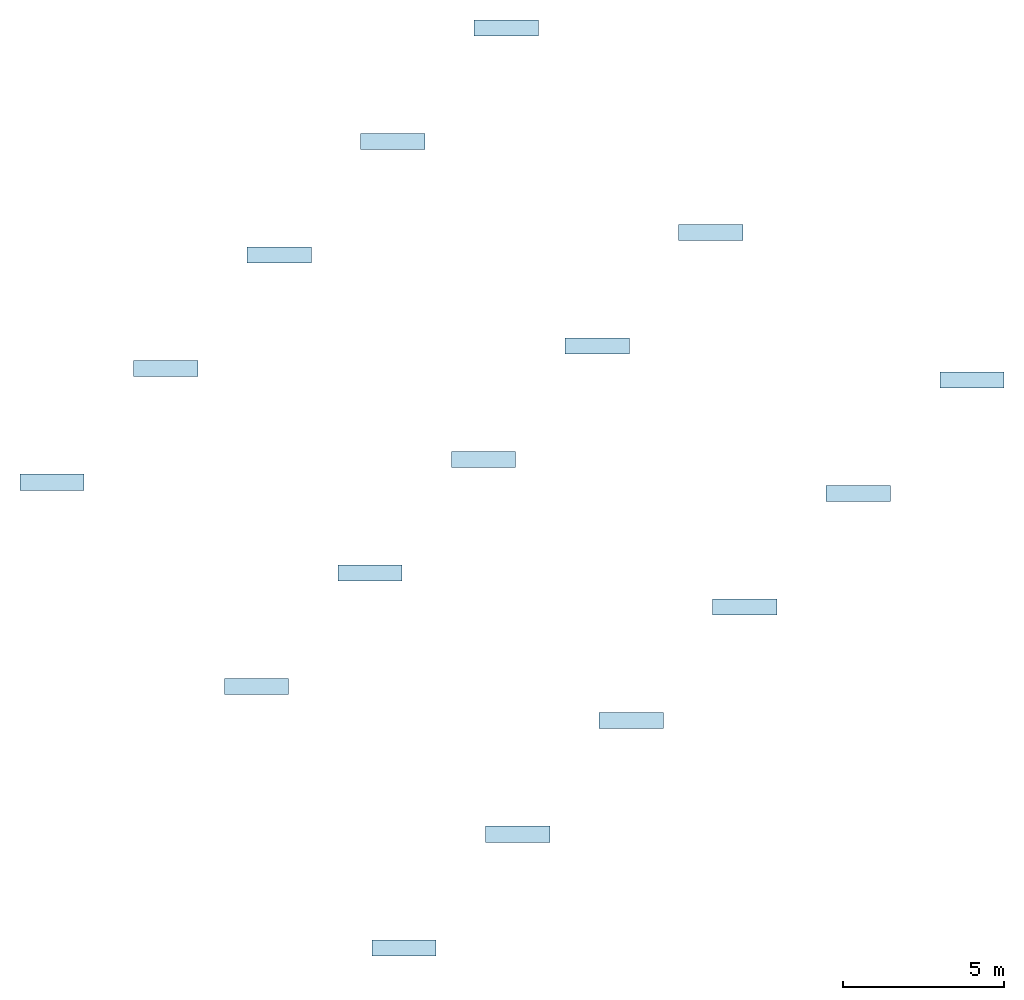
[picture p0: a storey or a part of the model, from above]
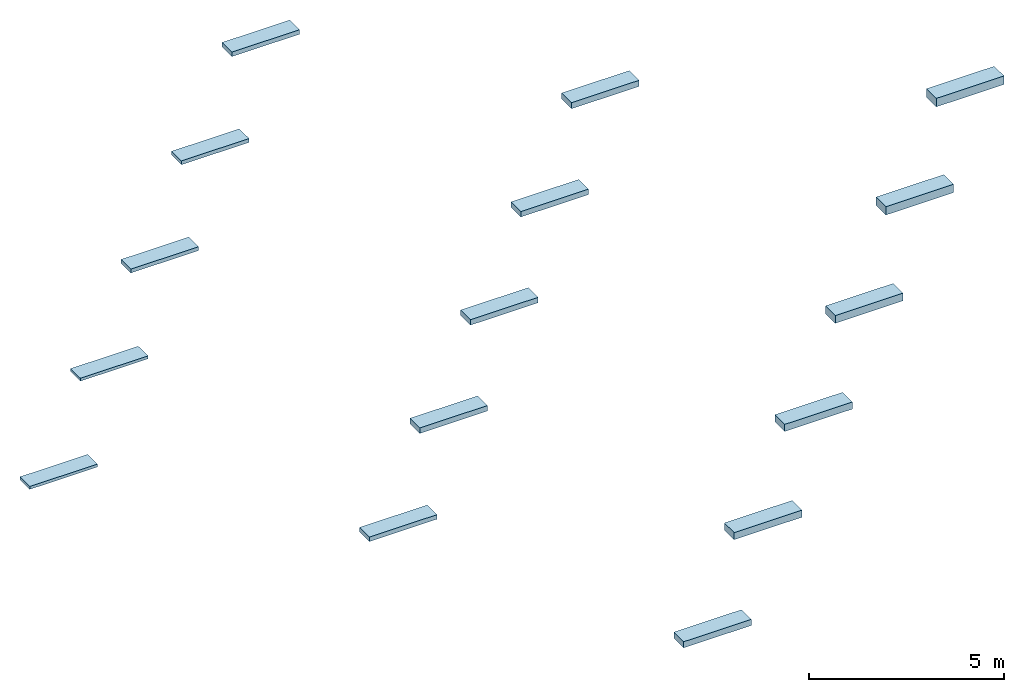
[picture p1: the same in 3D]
Properties of the parts of a building model (IFC2X3), part 2 of 3

# IfcSlab: Floor:NLRS_23_FL_Naturoll 037_120x580x6500mm, Floor:NLRS_23_FL_Naturoll 037_120x580x6500mm:13054
Type - Pset_ReinforcementBarPitchOfSlab - Description: Naturoll 037 - 120mm; Reference: NLRS_23_FL_Naturoll 037_120x580x6500mm
Type - Pset_SlabCommon - IsExternal: no; Reference: NLRS_23_FL_Naturoll 037_120x580x6500mm; ThermalTransmittance: 0.291667 kg/K/s3
Classification: 23 Vloeren (Uniformat)
Pset_SlabCommon - LoadBearing: no; PitchAngle: 0 deg
BaseQuantities - GrossArea: 1 m2; NetArea: 2.6 m2; GrossVolume: 120 m3; NetVolume: 0.12 m3; Perimeter: 5000 mm; Width: 120 mm
Constraints - Height Offset From Level: 0 mm; Level: Level: Begane grond; Related to Mass: no; Room Bounding: yes
Dimensions - Elevation at Top: 0 mm; Area: 1 m2; Elevation at Bottom: -120 mm; Perimeter: 5000 mm; Thickness: 120 mm; Volume: 0.12 m3
Other - Family: Floor: NLRS_23_FL_Naturoll 037_120x580x6500mm; Family and Type: Floor: NLRS_23_FL_Naturoll 037_120x580x6500mm; Type: Floor: NLRS_23_FL_Naturoll 037_120x580x6500mm; Type Id: Floor: NLRS_23_FL_Naturoll 037_120x580x6500mm
Phasing - Phase Created: New Construction
Structural - Enable Analytical Model: no; Structural: no

# IfcSlab: Floor:NLRS_23_FL_Naturoll 037_140x380x5600mm, Floor:NLRS_23_FL_Naturoll 037_140x380x5600mm:13079
In: Begane grond
Type - PredefinedType: FLOOR; Material: Knauf Insulation_Ecose® glaswol_naturoll 037 140 mm
Type - Analytical Properties - Roughness: 1; Thermal mass: 0; Absorptance: 0.1; Heat Transfer Coefficient (U): 0.25; Thermal Resistance (R): 4
Type - Construction - Function: Interior; Default Thickness: 140 mm
Type - Data - rollen / pak: 3; pak (m2): 6.38; pakken / pallet: 24; pallet (m2): 153.22
Type - Energy Analysis - kortstondige waterabsorptie: WS; langdurige waterabsorptie: WL(P); luchtstroomweerstand: Afr5; warmtegeleidingscoëfficiënt: 0.035; warmteweerstand: 3.75
Type - General - NLRS_C_content_creator: Cadix; NLRS_C_content_versie: V1.0
Type - Graphics - Coarse Scale Fill Color: 0
Type - Identity Data - Type Image: Raster image: Naturoll 037.jpg (3); Assembly Code: 23; Assembly Description: Vloeren; Description: Naturoll 037 - 140mm; DoP nummer (Declaration of performance): G4220JPCPR; email: customerservice.nl@knaufinsulation.com; Manufacturer: Knauf Insulation B.V.; Model: Naturoll 037 is een onbeklede glaswoldeken met ECOSE® Technology; NLRS_C_Code_Brandklasse: A1; phone: +31(0)162-421245; product URL: https://www.knaufinsulation.nl/producten-van-knauf-insulation/naturoll-037; Type Name: NLRS_23_FL_Naturoll 037_140x380x5600mm; URL: www.knaufinsulation.nl
Type - Model Properties - diktebereik: 20-370; diktetolerantie: T2
Type - Other - Category: Floors; Family Name: Floor
Type - Pset_ElementShading - Roughness: 304.8 mm
Type - Pset_ManufacturerTypeInformation - Manufacturer: Knauf Insulation B.V.
Type - Pset_ProductRequirements - Category: Floors
Type - Pset_QuantityTakeOff - Reference: NLRS_23_FL_Naturoll 037_140x380x5600mm
Type - Pset_ReinforcementBarPitchOfSlab - Description: Naturoll 037 - 140mm; Reference: NLRS_23_FL_Naturoll 037_140x380x5600mm
Type - Pset_SlabCommon - IsExternal: no; Reference: NLRS_23_FL_Naturoll 037_140x380x5600mm; ThermalTransmittance: 0.25 kg/K/s3
Classification: 23 Vloeren (Uniformat)
Pset_SlabCommon - LoadBearing: no; PitchAngle: 0 deg
BaseQuantities - GrossArea: 1 m2; NetArea: 2.7 m2; GrossVolume: 140 m3; NetVolume: 0.14 m3; Perimeter: 5000 mm; Width: 140 mm
Constraints - Height Offset From Level: 0 mm; Related to Mass: no; Room Bounding: yes; Level: Level: Begane grond
Dimensions - Elevation at Top: 0 mm; Area: 1 m2; Elevation at Bottom: -140 mm; Perimeter: 5000 mm; Thickness: 140 mm; Volume: 0.14 m3
Other - Family: Floor: NLRS_23_FL_Naturoll 037_140x380x5600mm; Family and Type: Floor: NLRS_23_FL_Naturoll 037_140x380x5600mm; Type: Floor: NLRS_23_FL_Naturoll 037_140x380x5600mm; Type Id: Floor: NLRS_23_FL_Naturoll 037_140x380x5600mm
Phasing - Phase Created: New Construction
Structural - Enable Analytical Model: no; Structural: no

# IfcSlab: Floor:NLRS_23_FL_Naturoll 037_140x580x5600mm, Floor:NLRS_23_FL_Naturoll 037_140x580x5600mm:13312
In: Begane grond
Type - PredefinedType: FLOOR; Material: Knauf Insulation_Ecose® glaswol_naturoll 037 140 mm
Type - Analytical Properties - Roughness: 1; Thermal mass: 0; Thermal Resistance (R): 4; Absorptance: 0.1; Heat Transfer Coefficient (U): 0.25
Type - Construction - Function: Interior; Default Thickness: 140 mm
Type - Data - rollen / pak: 2; pak (m2): 6.5; pakken / pallet: 24; pallet (m2): 155.9
Type - Energy Analysis - kortstondige waterabsorptie: WS; langdurige waterabsorptie: WL(P); luchtstroomweerstand: Afr5; warmtegeleidingscoëfficiënt: 0.035; warmteweerstand: 3.75
Type - General - NLRS_C_content_creator: Cadix; NLRS_C_content_versie: V1.0
Type - Graphics - Coarse Scale Fill Color: 0
Type - Identity Data - Type Image: Raster image: Naturoll 037.jpg (3); Assembly Code: 23; Assembly Description: Vloeren; Description: Naturoll 037 - 140mm; DoP nummer (Declaration of performance): G4220JPCPR; email: customerservice.nl@knaufinsulation.com; Manufacturer: Knauf Insulation B.V.; Model: Naturoll 037 is een onbeklede glaswoldeken met ECOSE® Technology; NLRS_C_Code_Brandklasse: A1; phone: +31(0)162-421245; product URL: https://www.knaufinsulation.nl/producten-van-knauf-insulation/naturoll-037; Type Name: NLRS_23_FL_Naturoll 037_140x580x5600mm; URL: www.knaufinsulation.nl
Type - Model Properties - diktebereik: 20-370; diktetolerantie: T2
Type - Other - Category: Floors; Family Name: Floor
Type - Pset_ElementShading - Roughness: 304.8 mm
Type - Pset_ManufacturerTypeInformation - Manufacturer: Knauf Insulation B.V.
Type - Pset_ProductRequirements - Category: Floors
Type - Pset_QuantityTakeOff - Reference: NLRS_23_FL_Naturoll 037_140x580x5600mm
Type - Pset_ReinforcementBarPitchOfSlab - Description: Naturoll 037 - 140mm; Reference: NLRS_23_FL_Naturoll 037_140x580x5600mm
Type - Pset_SlabCommon - IsExternal: no; ThermalTransmittance: 0.25 kg/K/s3; Reference: NLRS_23_FL_Naturoll 037_140x580x5600mm
Classification: 23 Vloeren (Uniformat)
Pset_SlabCommon - LoadBearing: no; PitchAngle: 0 deg
BaseQuantities - GrossArea: 1 m2; NetArea: 2.7 m2; GrossVolume: 140 m3; NetVolume: 0.14 m3; Perimeter: 5000 mm; Width: 140 mm
Constraints - Height Offset From Level: 0 mm; Related to Mass: no; Room Bounding: yes; Level: Level: Begane grond
Dimensions - Elevation at Top: 0 mm; Area: 1 m2; Elevation at Bottom: -140 mm; Perimeter: 5000 mm; Thickness: 140 mm; Volume: 0.14 m3
Other - Family: Floor: NLRS_23_FL_Naturoll 037_140x580x5600mm; Family and Type: Floor: NLRS_23_FL_Naturoll 037_140x580x5600mm; Type: Floor: NLRS_23_FL_Naturoll 037_140x580x5600mm; Type Id: Floor: NLRS_23_FL_Naturoll 037_140x580x5600mm
Phasing - Phase Created: New Construction
Structural - Enable Analytical Model: no; Structural: no

# IfcSlab: Floor:NLRS_23_FL_Naturoll 037_170x380x5600mm, Floor:NLRS_23_FL_Naturoll 037_170x380x5600mm:13334
In: Begane grond
Type - PredefinedType: FLOOR; Material: Knauf Insulation_Ecose® glaswol_naturoll 037 170 mm
Type - Analytical Properties - Roughness: 1; Thermal mass: 0; Absorptance: 0.1; Heat Transfer Coefficient (U): 0.205882; Thermal Resistance (R): 4.85714
Type - Construction - Function: Interior; Default Thickness: 170 mm
Type - Data - rollen / pak: 3; pak (m2): 5.24; pakken / pallet: 24; pallet (m2): 125.86
Type - Energy Analysis - kortstondige waterabsorptie: WS; langdurige waterabsorptie: WL(P); luchtstroomweerstand: Afr5; warmtegeleidingscoëfficiënt: 0.035; warmteweerstand: 4.55
Type - General - NLRS_C_content_creator: Cadix; NLRS_C_content_versie: V1.0
Type - Graphics - Coarse Scale Fill Color: 0
Type - Identity Data - Type Image: Raster image: Naturoll 037.jpg (3); Assembly Code: 23; Assembly Description: Vloeren; Description: Naturoll 037 - 170mm; DoP nummer (Declaration of performance): G4220JPCPR; email: customerservice.nl@knaufinsulation.com; Manufacturer: Knauf Insulation B.V.; Model: Naturoll 037 is een onbeklede glaswoldeken met ECOSE® Technology; NLRS_C_Code_Brandklasse: A1; phone: +31(0)162-421245; product URL: https://www.knaufinsulation.nl/producten-van-knauf-insulation/naturoll-037; Type Name: NLRS_23_FL_Naturoll 037_170x380x5600mm; URL: www.knaufinsulation.nl
Type - Model Properties - diktebereik: 20-370; diktetolerantie: T2
Type - Other - Category: Floors; Family Name: Floor
Type - Pset_ElementShading - Roughness: 304.8 mm
Type - Pset_ManufacturerTypeInformation - Manufacturer: Knauf Insulation B.V.
Type - Pset_ProductRequirements - Category: Floors
Type - Pset_QuantityTakeOff - Reference: NLRS_23_FL_Naturoll 037_170x380x5600mm
Type - Pset_ReinforcementBarPitchOfSlab - Description: Naturoll 037 - 170mm; Reference: NLRS_23_FL_Naturoll 037_170x380x5600mm
Type - Pset_SlabCommon - IsExternal: no; Reference: NLRS_23_FL_Naturoll 037_170x380x5600mm; ThermalTransmittance: 0.205882 kg/K/s3
Classification: 23 Vloeren (Uniformat)
Pset_SlabCommon - LoadBearing: no; PitchAngle: 0 deg
BaseQuantities - GrossArea: 1 m2; NetArea: 2.85 m2; GrossVolume: 170 m3; NetVolume: 0.17 m3; Perimeter: 5000 mm; Width: 170 mm
Constraints - Height Offset From Level: 0 mm; Related to Mass: no; Room Bounding: yes; Level: Level: Begane grond
Dimensions - Elevation at Top: 0 mm; Area: 1 m2; Elevation at Bottom: -170 mm; Perimeter: 5000 mm; Thickness: 170 mm; Volume: 0.17 m3
Other - Family: Floor: NLRS_23_FL_Naturoll 037_170x380x5600mm; Family and Type: Floor: NLRS_23_FL_Naturoll 037_170x380x5600mm; Type: Floor: NLRS_23_FL_Naturoll 037_170x380x5600mm; Type Id: Floor: NLRS_23_FL_Naturoll 037_170x380x5600mm
Phasing - Phase Created: New Construction
Structural - Enable Analytical Model: no; Structural: no

# IfcSlab: Floor:NLRS_23_FL_Naturoll 037_170x580x5600mm, Floor:NLRS_23_FL_Naturoll 037_170x580x5600mm:13356
In: Begane grond
Type - PredefinedType: FLOOR; Material: Knauf Insulation_Ecose® glaswol_naturoll 037 170 mm
Type - Analytical Properties - Roughness: 1; Thermal mass: 0; Absorptance: 0.1; Heat Transfer Coefficient (U): 0.205882; Thermal Resistance (R): 4.85714
Type - Construction - Function: Interior; Default Thickness: 170 mm
Type - Data - rollen / pak: 2; pak (m2): 5.34; pakken / pallet: 24; pallet (m2): 128.06
Type - Energy Analysis - kortstondige waterabsorptie: WS; langdurige waterabsorptie: WL(P); luchtstroomweerstand: Afr5; warmtegeleidingscoëfficiënt: 0.035; warmteweerstand: 4.55
Type - General - NLRS_C_content_creator: Cadix; NLRS_C_content_versie: V1.0
Type - Graphics - Coarse Scale Fill Color: 0
Type - Identity Data - Type Image: Raster image: Naturoll 037.jpg (3); Assembly Code: 23; Assembly Description: Vloeren; Description: Naturoll 037 - 170mm; DoP nummer (Declaration of performance): G4220JPCPR; email: customerservice.nl@knaufinsulation.com; Manufacturer: Knauf Insulation B.V.; Model: Naturoll 037 is een onbeklede glaswoldeken met ECOSE® Technology; NLRS_C_Code_Brandklasse: A1; phone: +31(0)162-421245; product URL: https://www.knaufinsulation.nl/producten-van-knauf-insulation/naturoll-037; Type Name: NLRS_23_FL_Naturoll 037_170x580x5600mm; URL: www.knaufinsulation.nl
Type - Model Properties - diktebereik: 20-370; diktetolerantie: T2
Type - Other - Category: Floors; Family Name: Floor
Type - Pset_ElementShading - Roughness: 304.8 mm
Type - Pset_ManufacturerTypeInformation - Manufacturer: Knauf Insulation B.V.
Type - Pset_ProductRequirements - Category: Floors
Type - Pset_QuantityTakeOff - Reference: NLRS_23_FL_Naturoll 037_170x580x5600mm
Type - Pset_ReinforcementBarPitchOfSlab - Description: Naturoll 037 - 170mm; Reference: NLRS_23_FL_Naturoll 037_170x580x5600mm
Type - Pset_SlabCommon - IsExternal: no; Reference: NLRS_23_FL_Naturoll 037_170x580x5600mm; ThermalTransmittance: 0.205882 kg/K/s3
Classification: 23 Vloeren (Uniformat)
Pset_SlabCommon - LoadBearing: no; PitchAngle: 0 deg
BaseQuantities - GrossArea: 1 m2; NetArea: 2.85 m2; GrossVolume: 170 m3; NetVolume: 0.17 m3; Perimeter: 5000 mm; Width: 170 mm
Constraints - Height Offset From Level: 0 mm; Level: Level: Begane grond; Related to Mass: no; Room Bounding: yes
Dimensions - Elevation at Top: 0 mm; Area: 1 m2; Elevation at Bottom: -170 mm; Perimeter: 5000 mm; Thickness: 170 mm; Volume: 0.17 m3
Other - Family: Floor: NLRS_23_FL_Naturoll 037_170x580x5600mm; Family and Type: Floor: NLRS_23_FL_Naturoll 037_170x580x5600mm; Type: Floor: NLRS_23_FL_Naturoll 037_170x580x5600mm; Type Id: Floor: NLRS_23_FL_Naturoll 037_170x580x5600mm
Phasing - Phase Created: New Construction
Structural - Enable Analytical Model: no; Structural: no

# IfcSlab: Floor:NLRS_23_FL_Naturoll 037_170x590x5600mm, Floor:NLRS_23_FL_Naturoll 037_170x590x5600mm:13378
In: Begane grond
Type - PredefinedType: FLOOR; Material: Knauf Insulation_Ecose® glaswol_naturoll 037 170 mm
Type - Analytical Properties - Roughness: 1; Thermal mass: 0; Absorptance: 0.1; Heat Transfer Coefficient (U): 0.205882; Thermal Resistance (R): 4.85714
Type - Construction - Function: Interior; Default Thickness: 170 mm
Type - Data - rollen / pak: 2; pak (m2): 5.43; pakken / pallet: 24; pallet (m2): 130.27
Type - Energy Analysis - kortstondige waterabsorptie: WS; langdurige waterabsorptie: WL(P); luchtstroomweerstand: Afr5; warmtegeleidingscoëfficiënt: 0.035; warmteweerstand: 4.55
Type - General - NLRS_C_content_creator: Cadix; NLRS_C_content_versie: V1.0
Type - Graphics - Coarse Scale Fill Color: 0
Type - Identity Data - Type Image: Raster image: Naturoll 037.jpg (3); Assembly Code: 23; Assembly Description: Vloeren; Description: Naturoll 037 - 170mm; DoP nummer (Declaration of performance): G4220JPCPR; email: customerservice.nl@knaufinsulation.com; Manufacturer: Knauf Insulation B.V.; Model: Naturoll 037 is een onbeklede glaswoldeken met ECOSE® Technology; NLRS_C_Code_Brandklasse: A1; phone: +31(0)162-421245; product URL: https://www.knaufinsulation.nl/producten-van-knauf-insulation/naturoll-037; Type Name: NLRS_23_FL_Naturoll 037_170x590x5600mm; URL: www.knaufinsulation.nl
Type - Model Properties - diktebereik: 20-370; diktetolerantie: T2
Type - Other - Category: Floors; Family Name: Floor
Type - Pset_ElementShading - Roughness: 304.8 mm
Type - Pset_ManufacturerTypeInformation - Manufacturer: Knauf Insulation B.V.
Type - Pset_ProductRequirements - Category: Floors
Type - Pset_QuantityTakeOff - Reference: NLRS_23_FL_Naturoll 037_170x590x5600mm
Type - Pset_ReinforcementBarPitchOfSlab - Description: Naturoll 037 - 170mm; Reference: NLRS_23_FL_Naturoll 037_170x590x5600mm
Type - Pset_SlabCommon - IsExternal: no; Reference: NLRS_23_FL_Naturoll 037_170x590x5600mm; ThermalTransmittance: 0.205882 kg/K/s3
Classification: 23 Vloeren (Uniformat)
Pset_SlabCommon - LoadBearing: no; PitchAngle: 0 deg
BaseQuantities - GrossArea: 1 m2; NetArea: 2.85 m2; GrossVolume: 170 m3; NetVolume: 0.17 m3; Perimeter: 5000 mm; Width: 170 mm
Constraints - Height Offset From Level: 0 mm; Related to Mass: no; Room Bounding: yes; Level: Level: Begane grond
Dimensions - Elevation at Top: 0 mm; Area: 1 m2; Elevation at Bottom: -170 mm; Perimeter: 5000 mm; Thickness: 170 mm; Volume: 0.17 m3
Other - Family: Floor: NLRS_23_FL_Naturoll 037_170x590x5600mm; Family and Type: Floor: NLRS_23_FL_Naturoll 037_170x590x5600mm; Type: Floor: NLRS_23_FL_Naturoll 037_170x590x5600mm; Type Id: Floor: NLRS_23_FL_Naturoll 037_170x590x5600mm
Phasing - Phase Created: New Construction
Structural - Enable Analytical Model: no; Structural: no

# IfcSlab: Floor:NLRS_23_FL_Naturoll 037_190x580x4100mm, Floor:NLRS_23_FL_Naturoll 037_190x580x4100mm:13400
In: Begane grond
Type - PredefinedType: FLOOR; Material: Knauf Insulation_Ecose® glaswol_naturoll 037 190 mm
Type - Analytical Properties - Roughness: 1; Thermal mass: 0; Absorptance: 0.1; Heat Transfer Coefficient (U): 0.184211; Thermal Resistance (R): 5.42857
Type - Construction - Function: Interior; Default Thickness: 190 mm
Type - Data - rollen / pak: 2; pak (m2): 4.76; pakken / pallet: 24; pallet (m2): 114.14
Type - Energy Analysis - kortstondige waterabsorptie: WS; langdurige waterabsorptie: WL(P); luchtstroomweerstand: Afr5; warmtegeleidingscoëfficiënt: 0.035; warmteweerstand: 5.1
Type - General - NLRS_C_content_creator: Cadix; NLRS_C_content_versie: V1.0
Type - Graphics - Coarse Scale Fill Color: 0
Type - Identity Data - Type Image: Raster image: Naturoll 037.jpg (3); Assembly Code: 23; Assembly Description: Vloeren; Description: Naturoll 037 - 190mm; DoP nummer (Declaration of performance): G4220JPCPR; email: customerservice.nl@knaufinsulation.com; Manufacturer: Knauf Insulation B.V.; Model: Naturoll 037 is een onbeklede glaswoldeken met ECOSE® Technology; NLRS_C_Code_Brandklasse: A1; phone: +31(0)162-421245; product URL: https://www.knaufinsulation.nl/producten-van-knauf-insulation/naturoll-037; Type Name: NLRS_23_FL_Naturoll 037_190x580x4100mm; URL: www.knaufinsulation.nl
Type - Model Properties - diktebereik: 20-370; diktetolerantie: T2
Type - Other - Category: Floors; Family Name: Floor
Type - Pset_ElementShading - Roughness: 304.8 mm
Type - Pset_ManufacturerTypeInformation - Manufacturer: Knauf Insulation B.V.
Type - Pset_ProductRequirements - Category: Floors
Type - Pset_QuantityTakeOff - Reference: NLRS_23_FL_Naturoll 037_190x580x4100mm
Type - Pset_ReinforcementBarPitchOfSlab - Description: Naturoll 037 - 190mm; Reference: NLRS_23_FL_Naturoll 037_190x580x4100mm
Type - Pset_SlabCommon - IsExternal: no; Reference: NLRS_23_FL_Naturoll 037_190x580x4100mm; ThermalTransmittance: 0.184211 kg/K/s3
Classification: 23 Vloeren (Uniformat)
Pset_SlabCommon - LoadBearing: no; PitchAngle: 0 deg
BaseQuantities - GrossArea: 1 m2; NetArea: 2.95 m2; GrossVolume: 190 m3; NetVolume: 0.19 m3; Perimeter: 5000 mm; Width: 190 mm
Constraints - Height Offset From Level: 0 mm; Related to Mass: no; Room Bounding: yes; Level: Level: Begane grond
Dimensions - Elevation at Top: 0 mm; Area: 1 m2; Elevation at Bottom: -190 mm; Perimeter: 5000 mm; Thickness: 190 mm; Volume: 0.19 m3
Other - Family: Floor: NLRS_23_FL_Naturoll 037_190x580x4100mm; Family and Type: Floor: NLRS_23_FL_Naturoll 037_190x580x4100mm; Type: Floor: NLRS_23_FL_Naturoll 037_190x580x4100mm; Type Id: Floor: NLRS_23_FL_Naturoll 037_190x580x4100mm
Phasing - Phase Created: New Construction
Structural - Enable Analytical Model: no; Structural: no

# IfcSlab: Floor:NLRS_23_FL_Naturoll 037_190x590x4100mm, Floor:NLRS_23_FL_Naturoll 037_190x590x4100mm:13499
In: Begane grond
Type - PredefinedType: FLOOR; Material: Knauf Insulation_Ecose® glaswol_naturoll 037 190 mm
Type - Analytical Properties - Roughness: 1; Thermal mass: 0; Absorptance: 0.1; Heat Transfer Coefficient (U): 0.184211; Thermal Resistance (R): 5.42857
Type - Construction - Function: Interior; Default Thickness: 190 mm
Type - Data - rollen / pak: 2; pak (m2): 4.84; pakken / pallet: 24; pallet (m2): 116.11
Type - Energy Analysis - kortstondige waterabsorptie: WS; langdurige waterabsorptie: WL(P); luchtstroomweerstand: Afr5; warmtegeleidingscoëfficiënt: 0.035; warmteweerstand: 5.1
Type - General - NLRS_C_content_creator: Cadix; NLRS_C_content_versie: V1.0
Type - Graphics - Coarse Scale Fill Color: 0
Type - Identity Data - Type Image: Raster image: Naturoll 037.jpg (3); Assembly Code: 23; Assembly Description: Vloeren; Description: Naturoll 037 - 190mm; DoP nummer (Declaration of performance): G4220JPCPR; email: customerservice.nl@knaufinsulation.com; Manufacturer: Knauf Insulation B.V.; Model: Naturoll 037 is een onbeklede glaswoldeken met ECOSE® Technology; NLRS_C_Code_Brandklasse: A1; phone: +31(0)162-421245; product URL: https://www.knaufinsulation.nl/producten-van-knauf-insulation/naturoll-037; Type Name: NLRS_23_FL_Naturoll 037_190x590x4100mm; URL: www.knaufinsulation.nl
Type - Model Properties - diktebereik: 20-370; diktetolerantie: T2
Type - Other - Category: Floors; Family Name: Floor
Type - Pset_ElementShading - Roughness: 304.8 mm
Type - Pset_ManufacturerTypeInformation - Manufacturer: Knauf Insulation B.V.
Type - Pset_ProductRequirements - Category: Floors
Type - Pset_QuantityTakeOff - Reference: NLRS_23_FL_Naturoll 037_190x590x4100mm
Type - Pset_ReinforcementBarPitchOfSlab - Description: Naturoll 037 - 190mm; Reference: NLRS_23_FL_Naturoll 037_190x590x4100mm
Type - Pset_SlabCommon - IsExternal: no; Reference: NLRS_23_FL_Naturoll 037_190x590x4100mm; ThermalTransmittance: 0.184211 kg/K/s3
Classification: 23 Vloeren (Uniformat)
Pset_SlabCommon - LoadBearing: no; PitchAngle: 0 deg
BaseQuantities - GrossArea: 1 m2; NetArea: 2.95 m2; GrossVolume: 190 m3; NetVolume: 0.19 m3; Perimeter: 5000 mm; Width: 190 mm
Constraints - Height Offset From Level: 0 mm; Related to Mass: no; Room Bounding: yes; Level: Level: Begane grond
Dimensions - Elevation at Top: 0 mm; Area: 1 m2; Elevation at Bottom: -190 mm; Perimeter: 5000 mm; Thickness: 190 mm; Volume: 0.19 m3
Other - Family: Floor: NLRS_23_FL_Naturoll 037_190x590x4100mm; Family and Type: Floor: NLRS_23_FL_Naturoll 037_190x590x4100mm; Type: Floor: NLRS_23_FL_Naturoll 037_190x590x4100mm; Type Id: Floor: NLRS_23_FL_Naturoll 037_190x590x4100mm
Phasing - Phase Created: New Construction
Structural - Enable Analytical Model: no; Structural: no

# IfcSlab: Floor:NLRS_23_FL_Naturoll 037_220x580x3500mm, Floor:NLRS_23_FL_Naturoll 037_220x580x3500mm:13519
In: Begane grond
Type - PredefinedType: FLOOR; Material: Knauf Insulation_Ecose® glaswol_naturoll 037 220 mm
Type - Analytical Properties - Roughness: 1; Thermal mass: 0; Absorptance: 0.1; Heat Transfer Coefficient (U): 0.159091; Thermal Resistance (R): 6.28571
Type - Construction - Function: Interior; Default Thickness: 220 mm
Type - Data - rollen / pak: 2; pak (m2): 4.06; pakken / pallet: 24; pallet (m2): 97.44
Type - Energy Analysis - kortstondige waterabsorptie: WS; langdurige waterabsorptie: WL(P); luchtstroomweerstand: Afr5; warmtegeleidingscoëfficiënt: 0.035; warmteweerstand: 5.9
Type - General - NLRS_C_content_creator: Cadix; NLRS_C_content_versie: V1.0
Type - Graphics - Coarse Scale Fill Color: 0
Type - Identity Data - Type Image: Raster image: Naturoll 037.jpg (3); Assembly Code: 23; Assembly Description: Vloeren; Description: Naturoll 037 - 220mm; DoP nummer (Declaration of performance): G4220JPCPR; email: customerservice.nl@knaufinsulation.com; Manufacturer: Knauf Insulation B.V.; Model: Naturoll 037 is een onbeklede glaswoldeken met ECOSE® Technology; NLRS_C_Code_Brandklasse: A1; phone: +31(0)162-421245; product URL: https://www.knaufinsulation.nl/producten-van-knauf-insulation/naturoll-037; Type Name: NLRS_23_FL_Naturoll 037_220x580x3500mm; URL: www.knaufinsulation.nl
Type - Model Properties - diktebereik: 20-370; diktetolerantie: T2
Type - Other - Category: Floors; Family Name: Floor
Type - Pset_ElementShading - Roughness: 304.8 mm
Type - Pset_ManufacturerTypeInformation - Manufacturer: Knauf Insulation B.V.
Type - Pset_ProductRequirements - Category: Floors
Type - Pset_QuantityTakeOff - Reference: NLRS_23_FL_Naturoll 037_220x580x3500mm
Type - Pset_ReinforcementBarPitchOfSlab - Description: Naturoll 037 - 220mm; Reference: NLRS_23_FL_Naturoll 037_220x580x3500mm
Type - Pset_SlabCommon - IsExternal: no; Reference: NLRS_23_FL_Naturoll 037_220x580x3500mm; ThermalTransmittance: 0.159091 kg/K/s3
Classification: 23 Vloeren (Uniformat)
Pset_SlabCommon - LoadBearing: no; PitchAngle: 0 deg
BaseQuantities - GrossArea: 1 m2; NetArea: 3.1 m2; GrossVolume: 220 m3; NetVolume: 0.22 m3; Perimeter: 5000 mm; Width: 220 mm
Constraints - Height Offset From Level: 0 mm; Level: Level: Begane grond; Related to Mass: no; Room Bounding: yes
Dimensions - Elevation at Top: 0 mm; Area: 1 m2; Elevation at Bottom: -220 mm; Perimeter: 5000 mm; Thickness: 220 mm; Volume: 0.22 m3
Other - Family: Floor: NLRS_23_FL_Naturoll 037_220x580x3500mm; Family and Type: Floor: NLRS_23_FL_Naturoll 037_220x580x3500mm; Type: Floor: NLRS_23_FL_Naturoll 037_220x580x3500mm; Type Id: Floor: NLRS_23_FL_Naturoll 037_220x580x3500mm
Phasing - Phase Created: New Construction
Structural - Enable Analytical Model: no; Structural: no

# IfcSlab: Floor:NLRS_23_FL_Naturoll 037_220x590x3500mm, Floor:NLRS_23_FL_Naturoll 037_220x590x3500mm:13539
In: Begane grond
Type - PredefinedType: FLOOR; Material: Knauf Insulation_Ecose® glaswol_naturoll 037 220 mm
Type - Analytical Properties - Roughness: 1; Thermal mass: 0; Absorptance: 0.1; Heat Transfer Coefficient (U): 0.159091; Thermal Resistance (R): 6.28571
Type - Construction - Function: Interior; Default Thickness: 220 mm
Type - Data - rollen / pak: 2; pak (m2): 4.13; pakken / pallet: 24; pallet (m2): 99.12
Type - Energy Analysis - kortstondige waterabsorptie: WS; langdurige waterabsorptie: WL(P); luchtstroomweerstand: Afr5; warmtegeleidingscoëfficiënt: 0.035; warmteweerstand: 5.9
Type - General - NLRS_C_content_creator: Cadix; NLRS_C_content_versie: V1.0
Type - Graphics - Coarse Scale Fill Color: 0
Type - Identity Data - Type Image: Raster image: Naturoll 037.jpg (3); Assembly Code: 23; Assembly Description: Vloeren; Description: Naturoll 037 - 220mm; DoP nummer (Declaration of performance): G4220JPCPR; email: customerservice.nl@knaufinsulation.com; Manufacturer: Knauf Insulation B.V.; Model: Naturoll 037 is een onbeklede glaswoldeken met ECOSE® Technology; NLRS_C_Code_Brandklasse: A1; phone: +31(0)162-421245; product URL: https://www.knaufinsulation.nl/producten-van-knauf-insulation/naturoll-037; Type Name: NLRS_23_FL_Naturoll 037_220x590x3500mm; URL: www.knaufinsulation.nl
Type - Model Properties - diktebereik: 20-370; diktetolerantie: T2
Type - Other - Category: Floors; Family Name: Floor
Type - Pset_ElementShading - Roughness: 304.8 mm
Type - Pset_ManufacturerTypeInformation - Manufacturer: Knauf Insulation B.V.
Type - Pset_ProductRequirements - Category: Floors
Type - Pset_QuantityTakeOff - Reference: NLRS_23_FL_Naturoll 037_220x590x3500mm
Type - Pset_ReinforcementBarPitchOfSlab - Description: Naturoll 037 - 220mm; Reference: NLRS_23_FL_Naturoll 037_220x590x3500mm
Type - Pset_SlabCommon - IsExternal: no; Reference: NLRS_23_FL_Naturoll 037_220x590x3500mm; ThermalTransmittance: 0.159091 kg/K/s3
Classification: 23 Vloeren (Uniformat)
Pset_SlabCommon - LoadBearing: no; PitchAngle: 0 deg
BaseQuantities - GrossArea: 1 m2; NetArea: 3.1 m2; GrossVolume: 220 m3; NetVolume: 0.22 m3; Perimeter: 5000 mm; Width: 220 mm
Constraints - Height Offset From Level: 0 mm; Level: Level: Begane grond; Related to Mass: no; Room Bounding: yes
Dimensions - Elevation at Top: 0 mm; Area: 1 m2; Elevation at Bottom: -220 mm; Perimeter: 5000 mm; Thickness: 220 mm; Volume: 0.22 m3
Other - Family: Floor: NLRS_23_FL_Naturoll 037_220x590x3500mm; Family and Type: Floor: NLRS_23_FL_Naturoll 037_220x590x3500mm; Type: Floor: NLRS_23_FL_Naturoll 037_220x590x3500mm; Type Id: Floor: NLRS_23_FL_Naturoll 037_220x590x3500mm
Phasing - Phase Created: New Construction
Structural - Enable Analytical Model: no; Structural: no

# IfcSlab: Floor:NLRS_23_FL_Naturoll 037_240x590x3250mm, Floor:NLRS_23_FL_Naturoll 037_240x590x3250mm:13559
In: Begane grond
Type - PredefinedType: FLOOR; Material: Knauf Insulation_Ecose® glaswol_naturoll 037 240 mm
Type - Analytical Properties - Roughness: 1; Thermal mass: 0; Absorptance: 0.1; Heat Transfer Coefficient (U): 0.145833; Thermal Resistance (R): 6.85714
Type - Construction - Function: Interior; Default Thickness: 240 mm
Type - Data - rollen / pak: 3; pak (m2): 3.84; pakken / pallet: 24; pallet (m2): 92.04
Type - Energy Analysis - kortstondige waterabsorptie: WS; langdurige waterabsorptie: WL(P); luchtstroomweerstand: Afr5; warmtegeleidingscoëfficiënt: 0.035; warmteweerstand: 6.45
Type - General - NLRS_C_content_creator: Cadix; NLRS_C_content_versie: V1.0
Type - Graphics - Coarse Scale Fill Color: 0
Type - Identity Data - Type Image: Raster image: Naturoll 037.jpg (3); Assembly Code: 23; Assembly Description: Vloeren; Description: Naturoll 037 - 240mm; DoP nummer (Declaration of performance): G4220JPCPR; email: customerservice.nl@knaufinsulation.com; Manufacturer: Knauf Insulation B.V.; Model: Naturoll 037 is een onbeklede glaswoldeken met ECOSE® Technology; NLRS_C_Code_Brandklasse: A1; phone: +31(0)162-421245; product URL: https://www.knaufinsulation.nl/producten-van-knauf-insulation/naturoll-037; Type Name: NLRS_23_FL_Naturoll 037_240x590x3250mm; URL: www.knaufinsulation.nl
Type - Model Properties - diktebereik: 20-370; diktetolerantie: T2
Type - Other - Category: Floors; Family Name: Floor
Type - Pset_ElementShading - Roughness: 304.8 mm
Type - Pset_ManufacturerTypeInformation - Manufacturer: Knauf Insulation B.V.
Type - Pset_ProductRequirements - Category: Floors
Type - Pset_QuantityTakeOff - Reference: NLRS_23_FL_Naturoll 037_240x590x3250mm
Type - Pset_ReinforcementBarPitchOfSlab - Description: Naturoll 037 - 240mm; Reference: NLRS_23_FL_Naturoll 037_240x590x3250mm
Type - Pset_SlabCommon - IsExternal: no; Reference: NLRS_23_FL_Naturoll 037_240x590x3250mm; ThermalTransmittance: 0.145833 kg/K/s3
Classification: 23 Vloeren (Uniformat)
Pset_SlabCommon - LoadBearing: no; PitchAngle: 0 deg
BaseQuantities - GrossArea: 1 m2; NetArea: 3.2 m2; GrossVolume: 240 m3; NetVolume: 0.24 m3; Perimeter: 5000 mm; Width: 240 mm
Constraints - Height Offset From Level: 0 mm; Related to Mass: no; Room Bounding: yes; Level: Level: Begane grond
Dimensions - Elevation at Top: 0 mm; Area: 1 m2; Elevation at Bottom: -240 mm; Perimeter: 5000 mm; Thickness: 240 mm; Volume: 0.24 m3
Other - Family: Floor: NLRS_23_FL_Naturoll 037_240x590x3250mm; Family and Type: Floor: NLRS_23_FL_Naturoll 037_240x590x3250mm; Type: Floor: NLRS_23_FL_Naturoll 037_240x590x3250mm; Type Id: Floor: NLRS_23_FL_Naturoll 037_240x590x3250mm
Phasing - Phase Created: New Construction
Structural - Enable Analytical Model: no; Structural: no

# IfcSlab: Floor:NLRS_23_FL_Naturoll 037_260x580x3000mm, Floor:NLRS_23_FL_Naturoll 037_260x580x3000mm:13579
In: Begane grond
Type - PredefinedType: FLOOR; Material: Knauf Insulation_Ecose® glaswol_naturoll 037 260 mm
Type - Analytical Properties - Roughness: 1; Thermal mass: 0; Absorptance: 0.1; Heat Transfer Coefficient (U): 0.134615; Thermal Resistance (R): 7.42857
Type - Construction - Function: Interior; Default Thickness: 260 mm
Type - Data - rollen / pak: 2; pak (m2): 3.48; pakken / pallet: 24; pallet (m2): 83.52
Type - Energy Analysis - kortstondige waterabsorptie: WS; langdurige waterabsorptie: WL(P); luchtstroomweerstand: Afr5; warmtegeleidingscoëfficiënt: 0.035; warmteweerstand: 7
Type - General - NLRS_C_content_creator: Cadix; NLRS_C_content_versie: V1.0
Type - Graphics - Coarse Scale Fill Color: 0
Type - Identity Data - Type Image: Raster image: Naturoll 037.jpg (3); Assembly Code: 23; Assembly Description: Vloeren; Description: Naturoll 037 - 260mm; DoP nummer (Declaration of performance): G4220JPCPR; email: customerservice.nl@knaufinsulation.com; Manufacturer: Knauf Insulation B.V.; Model: Naturoll 037 is een onbeklede glaswoldeken met ECOSE® Technology; NLRS_C_Code_Brandklasse: A1; phone: +31(0)162-421245; product URL: https://www.knaufinsulation.nl/producten-van-knauf-insulation/naturoll-037; Type Name: NLRS_23_FL_Naturoll 037_260x580x3000mm; URL: www.knaufinsulation.nl
Type - Model Properties - diktebereik: 20-370; diktetolerantie: T2
Type - Other - Category: Floors; Family Name: Floor
Type - Pset_ElementShading - Roughness: 304.8 mm
Type - Pset_ManufacturerTypeInformation - Manufacturer: Knauf Insulation B.V.
Type - Pset_ProductRequirements - Category: Floors
Type - Pset_QuantityTakeOff - Reference: NLRS_23_FL_Naturoll 037_260x580x3000mm
Type - Pset_ReinforcementBarPitchOfSlab - Description: Naturoll 037 - 260mm; Reference: NLRS_23_FL_Naturoll 037_260x580x3000mm
Type - Pset_SlabCommon - IsExternal: no; Reference: NLRS_23_FL_Naturoll 037_260x580x3000mm; ThermalTransmittance: 0.134615 kg/K/s3
Classification: 23 Vloeren (Uniformat)
Pset_SlabCommon - LoadBearing: no; PitchAngle: 0 deg
BaseQuantities - GrossArea: 1 m2; NetArea: 3.3 m2; GrossVolume: 260 m3; NetVolume: 0.26 m3; Perimeter: 5000 mm; Width: 260 mm
Constraints - Height Offset From Level: 0 mm; Level: Level: Begane grond; Related to Mass: no; Room Bounding: yes
Dimensions - Elevation at Top: 0 mm; Area: 1 m2; Elevation at Bottom: -260 mm; Perimeter: 5000 mm; Thickness: 260 mm; Volume: 0.26 m3
Other - Family: Floor: NLRS_23_FL_Naturoll 037_260x580x3000mm; Family and Type: Floor: NLRS_23_FL_Naturoll 037_260x580x3000mm; Type: Floor: NLRS_23_FL_Naturoll 037_260x580x3000mm; Type Id: Floor: NLRS_23_FL_Naturoll 037_260x580x3000mm
Phasing - Phase Created: New Construction
Structural - Enable Analytical Model: no; Structural: no

# IfcSlab: Floor:NLRS_23_FL_Naturoll 037_265x590x3000mm, Floor:NLRS_23_FL_Naturoll 037_265x590x3000mm:13717
In: Begane grond
Type - PredefinedType: FLOOR; Material: Knauf Insulation_Ecose® glaswol_naturoll 037 265 mm
Type - Analytical Properties - Roughness: 1; Thermal mass: 0; Absorptance: 0.1; Heat Transfer Coefficient (U): 0.132075; Thermal Resistance (R): 7.57143
Type - Construction - Function: Interior; Default Thickness: 265 mm
Type - Data - rollen / pak: 2; pak (m2): 3.54; pakken / pallet: 24; pallet (m2): 84.96
Type - Energy Analysis - kortstondige waterabsorptie: WS; langdurige waterabsorptie: WL(P); luchtstroomweerstand: Afr5; warmtegeleidingscoëfficiënt: 0.035; warmteweerstand: 7.1
Type - General - NLRS_C_content_creator: Cadix; NLRS_C_content_versie: V1.0
Type - Graphics - Coarse Scale Fill Color: 0
Type - Identity Data - Type Image: Raster image: Naturoll 037.jpg (3); Assembly Code: 23; Assembly Description: Vloeren; Description: Naturoll 037 - 265mm; DoP nummer (Declaration of performance): G4220JPCPR; email: customerservice.nl@knaufinsulation.com; Manufacturer: Knauf Insulation B.V.; Model: Naturoll 037 is een onbeklede glaswoldeken met ECOSE® Technology; NLRS_C_Code_Brandklasse: A1; phone: +31(0)162-421245; product URL: https://www.knaufinsulation.nl/producten-van-knauf-insulation/naturoll-037; Type Name: NLRS_23_FL_Naturoll 037_265x590x3000mm; URL: www.knaufinsulation.nl
Type - Model Properties - diktebereik: 20-370; diktetolerantie: T2
Type - Other - Category: Floors; Family Name: Floor
Type - Pset_ElementShading - Roughness: 304.8 mm
Type - Pset_ManufacturerTypeInformation - Manufacturer: Knauf Insulation B.V.
Type - Pset_ProductRequirements - Category: Floors
Type - Pset_QuantityTakeOff - Reference: NLRS_23_FL_Naturoll 037_265x590x3000mm
Type - Pset_ReinforcementBarPitchOfSlab - Description: Naturoll 037 - 265mm; Reference: NLRS_23_FL_Naturoll 037_265x590x3000mm
Type - Pset_SlabCommon - IsExternal: no; Reference: NLRS_23_FL_Naturoll 037_265x590x3000mm; ThermalTransmittance: 0.132075 kg/K/s3
Classification: 23 Vloeren (Uniformat)
Pset_SlabCommon - LoadBearing: no; PitchAngle: 0 deg
BaseQuantities - GrossArea: 1 m2; NetArea: 3.325 m2; GrossVolume: 265 m3; NetVolume: 0.265 m3; Perimeter: 5000 mm; Width: 265 mm
Constraints - Height Offset From Level: 0 mm; Level: Level: Begane grond; Related to Mass: no; Room Bounding: yes
Dimensions - Elevation at Top: 0 mm; Area: 1 m2; Elevation at Bottom: -265 mm; Perimeter: 5000 mm; Thickness: 265 mm; Volume: 0.265 m3
Other - Family: Floor: NLRS_23_FL_Naturoll 037_265x590x3000mm; Family and Type: Floor: NLRS_23_FL_Naturoll 037_265x590x3000mm; Type: Floor: NLRS_23_FL_Naturoll 037_265x590x3000mm; Type Id: Floor: NLRS_23_FL_Naturoll 037_265x590x3000mm
Phasing - Phase Created: New Construction
Structural - Enable Analytical Model: no; Structural: no

# IfcSlab: Floor:NLRS_23_FL_Naturoll 037_90x380x8200mm, Floor:NLRS_23_FL_Naturoll 037_90x380x8200mm:11523
In: Begane grond
Type - PredefinedType: FLOOR; Material: Knauf Insulation_Ecose® glaswol_naturoll 037 90 mm
Type - Analytical Properties - Absorptance: 0.1; Heat Transfer Coefficient (U): 0.388889; Roughness: 1; Thermal mass: 0; Thermal Resistance (R): 2.57143
Type - Construction - Default Thickness: 90 mm; Function: Interior
Type - Data - pak (m2): 9.35; pakken / pallet: 24; pallet (m2): 224.35; rollen / pak: 3
Type - Energy Analysis - kortstondige waterabsorptie: WS; langdurige waterabsorptie: WL(P); luchtstroomweerstand: Afr5; warmtegeleidingscoëfficiënt: 0.035; warmteweerstand: 2.4
Type - General - NLRS_C_content_creator: Cadix; NLRS_C_content_versie: V1.0
Type - Graphics - Coarse Scale Fill Color: 0
Type - Identity Data - Assembly Code: 23; Assembly Description: Vloeren; Description: Naturoll 037 - 90mm; DoP nummer (Declaration of performance): G4220JPCPR; email: customerservice.nl@knaufinsulation.com; Manufacturer: Knauf Insulation B.V.; Model: Naturoll 037 is een onbeklede glaswoldeken met ECOSE® Technology; NLRS_C_Code_Brandklasse: A1; phone: +31(0)162-421245; product URL: https://www.knaufinsulation.nl/producten-van-knauf-insulation/naturoll-037; Type Image: Raster image: Naturoll 037.jpg (3); Type Name: NLRS_23_FL_Naturoll 037_90x380x8200mm; URL: www.knaufinsulation.nl
Type - Model Properties - diktebereik: 20-370; diktetolerantie: T2
Type - Other - Category: Floors; Family Name: Floor
Type - Pset_ElementShading - Roughness: 304.8 mm
Type - Pset_ManufacturerTypeInformation - Manufacturer: Knauf Insulation B.V.
Type - Pset_ProductRequirements - Category: Floors
Type - Pset_QuantityTakeOff - Reference: NLRS_23_FL_Naturoll 037_90x380x8200mm
Type - Pset_ReinforcementBarPitchOfSlab - Description: Naturoll 037 - 90mm; Reference: NLRS_23_FL_Naturoll 037_90x380x8200mm
Type - Pset_SlabCommon - Reference: NLRS_23_FL_Naturoll 037_90x380x8200mm; IsExternal: no; ThermalTransmittance: 0.388889 kg/K/s3
Classification: 23 Vloeren (Uniformat)
Pset_SlabCommon - LoadBearing: no; PitchAngle: 0 deg
BaseQuantities - GrossArea: 1 m2; NetArea: 2.45 m2; GrossVolume: 90 m3; NetVolume: 0.09 m3; Perimeter: 5000 mm; Width: 90 mm
Constraints - Height Offset From Level: 0 mm; Level: Level: Begane grond; Related to Mass: no; Room Bounding: yes
Dimensions - Area: 1 m2; Elevation at Bottom: -90 mm; Elevation at Top: 0 mm; Perimeter: 5000 mm; Thickness: 90 mm; Volume: 0.09 m3
Other - Family: Floor: NLRS_23_FL_Naturoll 037_90x380x8200mm; Family and Type: Floor: NLRS_23_FL_Naturoll 037_90x380x8200mm; Type: Floor: NLRS_23_FL_Naturoll 037_90x380x8200mm; Type Id: Floor: NLRS_23_FL_Naturoll 037_90x380x8200mm
Phasing - Phase Created: New Construction
Structural - Enable Analytical Model: no; Structural: no

# IfcSlab: Floor:NLRS_23_FL_Naturoll 037_90x580x8200mm, Floor:NLRS_23_FL_Naturoll 037_90x580x8200mm:12977
In: Begane grond
Type - PredefinedType: FLOOR; Material: Knauf Insulation_Ecose® glaswol_naturoll 037 90 mm
Type - Analytical Properties - Roughness: 1; Thermal mass: 0; Absorptance: 0.1; Heat Transfer Coefficient (U): 0.388889; Thermal Resistance (R): 2.57143
Type - Construction - Function: Interior; Default Thickness: 90 mm
Type - Data - pak (m2): 9.51; pakken / pallet: 24; pallet (m2): 228.29; rollen / pak: 2
Type - Energy Analysis - kortstondige waterabsorptie: WS; langdurige waterabsorptie: WL(P); luchtstroomweerstand: Afr5; warmtegeleidingscoëfficiënt: 0.035; warmteweerstand: 2.4
Type - General - NLRS_C_content_creator: Cadix; NLRS_C_content_versie: V1.0
Type - Graphics - Coarse Scale Fill Color: 0
Type - Identity Data - Type Image: Raster image: Naturoll 037.jpg (3); Assembly Code: 23; Assembly Description: Vloeren; Description: Naturoll 037 - 90mm; DoP nummer (Declaration of performance): G4220JPCPR; email: customerservice.nl@knaufinsulation.com; Manufacturer: Knauf Insulation B.V.; Model: Naturoll 037 is een onbeklede glaswoldeken met ECOSE® Technology; NLRS_C_Code_Brandklasse: A1; phone: +31(0)162-421245; product URL: https://www.knaufinsulation.nl/producten-van-knauf-insulation/naturoll-037; Type Name: NLRS_23_FL_Naturoll 037_90x580x8200mm; URL: www.knaufinsulation.nl
Type - Model Properties - diktebereik: 20-370; diktetolerantie: T2
Type - Other - Category: Floors; Family Name: Floor
Type - Pset_ElementShading - Roughness: 304.8 mm
Type - Pset_ManufacturerTypeInformation - Manufacturer: Knauf Insulation B.V.
Type - Pset_ProductRequirements - Category: Floors
Type - Pset_QuantityTakeOff - Reference: NLRS_23_FL_Naturoll 037_90x580x8200mm
Type - Pset_ReinforcementBarPitchOfSlab - Description: Naturoll 037 - 90mm; Reference: NLRS_23_FL_Naturoll 037_90x580x8200mm
Type - Pset_SlabCommon - IsExternal: no; Reference: NLRS_23_FL_Naturoll 037_90x580x8200mm; ThermalTransmittance: 0.388889 kg/K/s3
Classification: 23 Vloeren (Uniformat)
Pset_SlabCommon - LoadBearing: no; PitchAngle: 0 deg
BaseQuantities - GrossArea: 1 m2; NetArea: 2.45 m2; GrossVolume: 90 m3; NetVolume: 0.09 m3; Perimeter: 5000 mm; Width: 90 mm
Constraints - Height Offset From Level: 0 mm; Related to Mass: no; Room Bounding: yes; Level: Level: Begane grond
Dimensions - Elevation at Top: 0 mm; Area: 1 m2; Elevation at Bottom: -90 mm; Perimeter: 5000 mm; Thickness: 90 mm; Volume: 0.09 m3
Other - Family: Floor: NLRS_23_FL_Naturoll 037_90x580x8200mm; Family and Type: Floor: NLRS_23_FL_Naturoll 037_90x580x8200mm; Type: Floor: NLRS_23_FL_Naturoll 037_90x580x8200mm; Type Id: Floor: NLRS_23_FL_Naturoll 037_90x580x8200mm
Phasing - Phase Created: New Construction
Structural - Enable Analytical Model: no; Structural: no

# IfcWallStandardCase: Basic Wall:NLRS_21_WA_Naturoll 037_120x380x6500mm (2)
In: Begane grond
Type - PredefinedType: STANDARD; Material: Knauf Insulation_Ecose® glaswol_naturoll 037 120 mm
Type - Analytical Properties - Roughness: 1; Thermal mass: 0; Absorptance: 0.1; Heat Transfer Coefficient (U): 0.291667; Thermal Resistance (R): 3.42857
Type - Construction - Function: Exterior; Wrapping at Inserts: Do not wrap; Width: 120 mm
Type - Data - rollen / pak: 3; pak (m2): 7.41; pakken / pallet: 24; pallet (m2): 177.84
Type - Energy Analysis - kortstondige waterabsorptie: WS; langdurige waterabsorptie: WL(P); luchtstroomweerstand: Afr5; warmtegeleidingscoëfficiënt: 0.035; warmteweerstand: 3.2
Type - General - NLRS_C_content_creator: Cadix; NLRS_C_content_versie: V1.0
Type - Graphics - Coarse Scale Fill Color: 0
Type - Identity Data - Type Image: Raster image: Naturoll 037.jpg (3); Assembly Code: 21; Assembly Description: Buitenwanden; Description: Naturoll 037 - 120mm; DoP nummer (Declaration of performance): G4220JPCPR; email: customerservice.nl@knaufinsulation.com; Manufacturer: Knauf Insulation B.V.; Model: Naturoll 037 is een onbeklede glaswoldeken met ECOSE® Technology; NLRS_C_Code_Brandklasse: A1; phone: +31(0)162-421245; product URL: https://www.knaufinsulation.nl/producten-van-knauf-insulation/naturoll-037; Type Name: NLRS_21_WA_Naturoll 037_120x380x6500mm; URL: www.knaufinsulation.nl
Type - Model Properties - diktebereik: 20-370; diktetolerantie: T2
Type - Other - Category: Walls; Family Name: Basic Wall
Type - Pset_ElementShading - Roughness: 304.8 mm
Type - Pset_ManufacturerTypeInformation - Manufacturer: Knauf Insulation B.V.
Type - Pset_ProductRequirements - Category: Walls
Type - Pset_QuantityTakeOff - Reference: NLRS_21_WA_Naturoll 037_120x380x6500mm
Type - Pset_ReinforcementBarPitchOfWall - Description: Naturoll 037 - 120mm; Reference: NLRS_21_WA_Naturoll 037_120x380x6500mm
Type - Pset_WallCommon - IsExternal: no; Reference: NLRS_21_WA_Naturoll 037_120x380x6500mm; ThermalTransmittance: 0.291667 kg/K/s3
Classification: 21 Buitenwanden (Uniformat)
BaseQuantities - Height: 2500 mm; Width: 120 mm
Constraints - Related to Mass: no; Room Bounding: yes; Base Constraint: Level: Begane grond; Base Extension Distance: 0 mm; Base is Attached: no; Base Offset: 0 mm; Top Constraint: Level: Lengte; Top Extension Distance: 0 mm; Top is Attached: no; Top Offset: 0 mm; Unconnected Height: 2500 mm
Other - Family: Basic Wall: NLRS_21_WA_Naturoll 037_120x380x6500mm; Family and Type: Basic Wall: NLRS_21_WA_Naturoll 037_120x380x6500mm; Type: Basic Wall: NLRS_21_WA_Naturoll 037_120x380x6500mm; Type Id: Basic Wall: NLRS_21_WA_Naturoll 037_120x380x6500mm
Phasing - Phase Created: New Construction
Structural - Enable Analytical Model: no; Structural: no; Structural Usage: Non-bearing
Pset_WallCommon - LoadBearing: no; IsExternal: yes; ExtendToStructure: no
Name (Basic Wall:NLRS_21_WA_Naturoll 037_120x380x6500mm:...) | BaseQuantities, Length (mm) = Dimensions, Length (mm) | GrossFootprintArea (m2) | NetVolume (m3) | NetSideArea (m2) | Location Line | Area (m2) | Volume (m3)
13034 | 2000 | 0.24 | 600000000 | 5000000 | Core Face: Interior | 5 | 0.6
13036 | 500 | 0.06 | 150000000 | 1250000 | Wall Centerline | 1.25 | 0.15

# IfcWallStandardCase: Basic Wall:NLRS_21_WA_Naturoll 037_120x580x6500mm (2)
In: Begane grond
Type - PredefinedType: STANDARD; Material: Knauf Insulation_Ecose® glaswol_naturoll 037 120 mm
Type - Analytical Properties - Roughness: 1; Thermal mass: 0; Absorptance: 0.1; Heat Transfer Coefficient (U): 0.291667; Thermal Resistance (R): 3.42857
Type - Construction - Function: Exterior; Wrapping at Inserts: Do not wrap; Width: 120 mm
Type - Data - rollen / pak: 2; pak (m2): 7.54; pakken / pallet: 24; pallet (m2): 180.96
Type - Energy Analysis - kortstondige waterabsorptie: WS; langdurige waterabsorptie: WL(P); luchtstroomweerstand: Afr5; warmtegeleidingscoëfficiënt: 0.035; warmteweerstand: 3.2
Type - General - NLRS_C_content_creator: Cadix; NLRS_C_content_versie: V1.0
Type - Graphics - Coarse Scale Fill Color: 0
Type - Identity Data - Type Image: Raster image: Naturoll 037.jpg (3); Assembly Code: 21; Assembly Description: Buitenwanden; Description: Naturoll 037 - 120mm; DoP nummer (Declaration of performance): G4220JPCPR; email: customerservice.nl@knaufinsulation.com; Manufacturer: Knauf Insulation B.V.; Model: Naturoll 037 is een onbeklede glaswoldeken met ECOSE® Technology; NLRS_C_Code_Brandklasse: A1; phone: +31(0)162-421245; product URL: https://www.knaufinsulation.nl/producten-van-knauf-insulation/naturoll-037; Type Name: NLRS_21_WA_Naturoll 037_120x580x6500mm; URL: www.knaufinsulation.nl
Type - Model Properties - diktebereik: 20-370; diktetolerantie: T2
Type - Other - Category: Walls; Family Name: Basic Wall
Type - Pset_ElementShading - Roughness: 304.8 mm
Type - Pset_ManufacturerTypeInformation - Manufacturer: Knauf Insulation B.V.
Type - Pset_ProductRequirements - Category: Walls
Type - Pset_QuantityTakeOff - Reference: NLRS_21_WA_Naturoll 037_120x580x6500mm
Type - Pset_ReinforcementBarPitchOfWall - Description: Naturoll 037 - 120mm; Reference: NLRS_21_WA_Naturoll 037_120x580x6500mm
Type - Pset_WallCommon - IsExternal: no; Reference: NLRS_21_WA_Naturoll 037_120x580x6500mm; ThermalTransmittance: 0.291667 kg/K/s3
Classification: 21 Buitenwanden (Uniformat)
BaseQuantities - Height: 2500 mm; Width: 120 mm
Constraints - Related to Mass: no; Room Bounding: yes; Base Constraint: Level: Begane grond; Base Extension Distance: 0 mm; Base is Attached: no; Base Offset: 0 mm; Top Constraint: Level: Lengte; Top Extension Distance: 0 mm; Top is Attached: no; Top Offset: 0 mm; Unconnected Height: 2500 mm
Other - Family: Basic Wall: NLRS_21_WA_Naturoll 037_120x580x6500mm; Family and Type: Basic Wall: NLRS_21_WA_Naturoll 037_120x580x6500mm; Type: Basic Wall: NLRS_21_WA_Naturoll 037_120x580x6500mm; Type Id: Basic Wall: NLRS_21_WA_Naturoll 037_120x580x6500mm
Phasing - Phase Created: New Construction
Structural - Enable Analytical Model: no; Structural: no; Structural Usage: Non-bearing
Pset_WallCommon - LoadBearing: no; IsExternal: yes; ExtendToStructure: no
Name (Basic Wall:NLRS_21_WA_Naturoll 037_120x580x6500mm:...) | BaseQuantities, Length (mm) = Dimensions, Length (mm) | GrossFootprintArea (m2) | NetVolume (m3) | NetSideArea (m2) | Location Line | Area (m2) | Volume (m3)
13059 | 2000 | 0.24 | 600000000 | 5000000 | Core Face: Interior | 5 | 0.6
13061 | 500 | 0.06 | 150000000 | 1250000 | Wall Centerline | 1.25 | 0.15

# IfcWallStandardCase: Basic Wall:NLRS_21_WA_Naturoll 037_140x380x5600mm (2)
In: Begane grond
Type - PredefinedType: STANDARD; Material: Knauf Insulation_Ecose® glaswol_naturoll 037 140 mm
Type - Analytical Properties - Roughness: 1; Thermal mass: 0; Thermal Resistance (R): 4; Absorptance: 0.1; Heat Transfer Coefficient (U): 0.25
Type - Construction - Function: Exterior; Wrapping at Inserts: Do not wrap; Width: 140 mm
Type - Data - rollen / pak: 3; pak (m2): 6.38; pakken / pallet: 24; pallet (m2): 153.22
Type - Energy Analysis - kortstondige waterabsorptie: WS; langdurige waterabsorptie: WL(P); luchtstroomweerstand: Afr5; warmtegeleidingscoëfficiënt: 0.035; warmteweerstand: 3.75
Type - General - NLRS_C_content_creator: Cadix; NLRS_C_content_versie: V1.0
Type - Graphics - Coarse Scale Fill Color: 0
Type - Identity Data - Type Image: Raster image: Naturoll 037.jpg (3); Assembly Code: 21; Assembly Description: Buitenwanden; Description: Naturoll 037 - 140mm; DoP nummer (Declaration of performance): G4220JPCPR; email: customerservice.nl@knaufinsulation.com; Manufacturer: Knauf Insulation B.V.; Model: Naturoll 037 is een onbeklede glaswoldeken met ECOSE® Technology; NLRS_C_Code_Brandklasse: A1; phone: +31(0)162-421245; product URL: https://www.knaufinsulation.nl/producten-van-knauf-insulation/naturoll-037; Type Name: NLRS_21_WA_Naturoll 037_140x380x5600mm; URL: www.knaufinsulation.nl
Type - Model Properties - diktebereik: 20-370; diktetolerantie: T2
Type - Other - Category: Walls; Family Name: Basic Wall
Type - Pset_ElementShading - Roughness: 304.8 mm
Type - Pset_ManufacturerTypeInformation - Manufacturer: Knauf Insulation B.V.
Type - Pset_ProductRequirements - Category: Walls
Type - Pset_QuantityTakeOff - Reference: NLRS_21_WA_Naturoll 037_140x380x5600mm
Type - Pset_ReinforcementBarPitchOfWall - Description: Naturoll 037 - 140mm; Reference: NLRS_21_WA_Naturoll 037_140x380x5600mm
Type - Pset_WallCommon - IsExternal: no; ThermalTransmittance: 0.25 kg/K/s3; Reference: NLRS_21_WA_Naturoll 037_140x380x5600mm
Classification: 21 Buitenwanden (Uniformat)
BaseQuantities - Height: 2500 mm; Width: 140 mm
Constraints - Related to Mass: no; Room Bounding: yes; Base Constraint: Level: Begane grond; Base Extension Distance: 0 mm; Base is Attached: no; Base Offset: 0 mm; Top Constraint: Level: Lengte; Top Extension Distance: 0 mm; Top is Attached: no; Top Offset: 0 mm; Unconnected Height: 2500 mm
Other - Family: Basic Wall: NLRS_21_WA_Naturoll 037_140x380x5600mm; Family and Type: Basic Wall: NLRS_21_WA_Naturoll 037_140x380x5600mm; Type: Basic Wall: NLRS_21_WA_Naturoll 037_140x380x5600mm; Type Id: Basic Wall: NLRS_21_WA_Naturoll 037_140x380x5600mm
Phasing - Phase Created: New Construction
Structural - Enable Analytical Model: no; Structural: no; Structural Usage: Non-bearing
Pset_WallCommon - LoadBearing: no; IsExternal: yes; ExtendToStructure: no
Name (Basic Wall:NLRS_21_WA_Naturoll 037_140x380x5600mm:...) | BaseQuantities, Length (mm) = Dimensions, Length (mm) | GrossFootprintArea (m2) | NetVolume (m3) | NetSideArea (m2) | Location Line | Area (m2) | Volume (m3)
13084 | 2000 | 0.28 | 700000000 | 5000000 | Core Face: Interior | 5 | 0.7
13086 | 500 | 0.07 | 175000000 | 1250000 | Wall Centerline | 1.25 | 0.175

# IfcWallStandardCase: Basic Wall:NLRS_21_WA_Naturoll 037_140x580x5600mm (2)
In: Begane grond
Type - PredefinedType: STANDARD; Material: Knauf Insulation_Ecose® glaswol_naturoll 037 140 mm
Type - Analytical Properties - Roughness: 1; Thermal mass: 0; Thermal Resistance (R): 4; Absorptance: 0.1; Heat Transfer Coefficient (U): 0.25
Type - Construction - Function: Exterior; Wrapping at Inserts: Do not wrap; Width: 140 mm
Type - Data - rollen / pak: 2; pak (m2): 6.5; pakken / pallet: 24; pallet (m2): 155.9
Type - Energy Analysis - kortstondige waterabsorptie: WS; langdurige waterabsorptie: WL(P); luchtstroomweerstand: Afr5; warmtegeleidingscoëfficiënt: 0.035; warmteweerstand: 3.75
Type - General - NLRS_C_content_creator: Cadix; NLRS_C_content_versie: V1.0
Type - Graphics - Coarse Scale Fill Color: 0
Type - Identity Data - Type Image: Raster image: Naturoll 037.jpg (3); Assembly Code: 21; Assembly Description: Buitenwanden; Description: Naturoll 037 - 140mm; DoP nummer (Declaration of performance): G4220JPCPR; email: customerservice.nl@knaufinsulation.com; Manufacturer: Knauf Insulation B.V.; Model: Naturoll 037 is een onbeklede glaswoldeken met ECOSE® Technology; NLRS_C_Code_Brandklasse: A1; phone: +31(0)162-421245; product URL: https://www.knaufinsulation.nl/producten-van-knauf-insulation/naturoll-037; Type Name: NLRS_21_WA_Naturoll 037_140x580x5600mm; URL: Knauf Insulation B.V.
Type - Model Properties - diktebereik: 20-370; diktetolerantie: T2
Type - Other - Category: Walls; Family Name: Basic Wall
Type - Pset_ElementShading - Roughness: 304.8 mm
Type - Pset_ManufacturerTypeInformation - Manufacturer: Knauf Insulation B.V.
Type - Pset_ProductRequirements - Category: Walls
Type - Pset_QuantityTakeOff - Reference: NLRS_21_WA_Naturoll 037_140x580x5600mm
Type - Pset_ReinforcementBarPitchOfWall - Description: Naturoll 037 - 140mm; Reference: NLRS_21_WA_Naturoll 037_140x580x5600mm
Type - Pset_WallCommon - IsExternal: no; ThermalTransmittance: 0.25 kg/K/s3; Reference: NLRS_21_WA_Naturoll 037_140x580x5600mm
Classification: 21 Buitenwanden (Uniformat)
BaseQuantities - Height: 2500 mm; Width: 140 mm
Constraints - Related to Mass: no; Room Bounding: yes; Base Constraint: Level: Begane grond; Base Extension Distance: 0 mm; Base is Attached: no; Base Offset: 0 mm; Top Constraint: Level: Lengte; Top Extension Distance: 0 mm; Top is Attached: no; Top Offset: 0 mm; Unconnected Height: 2500 mm
Other - Family: Basic Wall: NLRS_21_WA_Naturoll 037_140x580x5600mm; Family and Type: Basic Wall: NLRS_21_WA_Naturoll 037_140x580x5600mm; Type: Basic Wall: NLRS_21_WA_Naturoll 037_140x580x5600mm; Type Id: Basic Wall: NLRS_21_WA_Naturoll 037_140x580x5600mm
Phasing - Phase Created: New Construction
Structural - Enable Analytical Model: no; Structural: no; Structural Usage: Non-bearing
Pset_WallCommon - LoadBearing: no; IsExternal: yes; ExtendToStructure: no
Name (Basic Wall:NLRS_21_WA_Naturoll 037_140x580x5600mm:...) | BaseQuantities, Length (mm) = Dimensions, Length (mm) | GrossFootprintArea (m2) | NetVolume (m3) | NetSideArea (m2) | Location Line | Area (m2) | Volume (m3)
13317 | 2000 | 0.28 | 700000000 | 5000000 | Core Face: Interior | 5 | 0.7
13319 | 500 | 0.07 | 175000000 | 1250000 | Wall Centerline | 1.25 | 0.175

# IfcWallStandardCase: Basic Wall:NLRS_21_WA_Naturoll 037_170x380x4600mm (2)
In: Begane grond
Type - PredefinedType: STANDARD; Material: Knauf Insulation_Ecose® glaswol_naturoll 037 170 mm
Type - Analytical Properties - Roughness: 1; Thermal mass: 0; Absorptance: 0.1; Heat Transfer Coefficient (U): 0.205882; Thermal Resistance (R): 4.85714
Type - Construction - Function: Exterior; Wrapping at Inserts: Do not wrap; Width: 170 mm
Type - Data - rollen / pak: 3; pak (m2): 5.24; pakken / pallet: 24; pallet (m2): 125.86
Type - Energy Analysis - kortstondige waterabsorptie: WS; langdurige waterabsorptie: WL(P); luchtstroomweerstand: Afr5; warmtegeleidingscoëfficiënt: 0.035; warmteweerstand: 4.55
Type - General - NLRS_C_content_creator: Cadix; NLRS_C_content_versie: V1.0
Type - Graphics - Coarse Scale Fill Color: 0
Type - Identity Data - Type Image: Raster image: Naturoll 037.jpg (3); Assembly Code: 21; Assembly Description: Buitenwanden; Description: Naturoll 037 - 170mm; DoP nummer (Declaration of performance): G4220JPCPR; email: customerservice.nl@knaufinsulation.com; Manufacturer: Knauf Insulation B.V.; Model: Naturoll 037 is een onbeklede glaswoldeken met ECOSE® Technology; NLRS_C_Code_Brandklasse: A1; phone: +31(0)162-421245; product URL: https://www.knaufinsulation.nl/producten-van-knauf-insulation/naturoll-037; Type Name: NLRS_21_WA_Naturoll 037_170x380x4600mm; URL: www.knaufinsulation.nl
Type - Model Properties - diktebereik: 20-370; diktetolerantie: T2
Type - Other - Category: Walls; Family Name: Basic Wall
Type - Pset_ElementShading - Roughness: 304.8 mm
Type - Pset_ManufacturerTypeInformation - Manufacturer: Knauf Insulation B.V.
Type - Pset_ProductRequirements - Category: Walls
Type - Pset_QuantityTakeOff - Reference: NLRS_21_WA_Naturoll 037_170x380x4600mm
Type - Pset_ReinforcementBarPitchOfWall - Description: Naturoll 037 - 170mm; Reference: NLRS_21_WA_Naturoll 037_170x380x4600mm
Type - Pset_WallCommon - IsExternal: no; Reference: NLRS_21_WA_Naturoll 037_170x380x4600mm; ThermalTransmittance: 0.205882 kg/K/s3
Classification: 21 Buitenwanden (Uniformat)
BaseQuantities - Height: 2500 mm; Width: 170 mm
Constraints - Related to Mass: no; Room Bounding: yes; Base Constraint: Level: Begane grond; Base Extension Distance: 0 mm; Base is Attached: no; Base Offset: 0 mm; Top Constraint: Level: Lengte; Top Extension Distance: 0 mm; Top is Attached: no; Top Offset: 0 mm; Unconnected Height: 2500 mm
Other - Family: Basic Wall: NLRS_21_WA_Naturoll 037_170x380x4600mm; Family and Type: Basic Wall: NLRS_21_WA_Naturoll 037_170x380x4600mm; Type: Basic Wall: NLRS_21_WA_Naturoll 037_170x380x4600mm; Type Id: Basic Wall: NLRS_21_WA_Naturoll 037_170x380x4600mm
Phasing - Phase Created: New Construction
Structural - Enable Analytical Model: no; Structural: no; Structural Usage: Non-bearing
Pset_WallCommon - LoadBearing: no; IsExternal: yes; ExtendToStructure: no
Name (Basic Wall:NLRS_21_WA_Naturoll 037_170x380x4600mm:...) | BaseQuantities, Length (mm) = Dimensions, Length (mm) | GrossFootprintArea (m2) | NetVolume (m3) | NetSideArea (m2) | Location Line | Area (m2) | Volume (m3)
13339 | 2000 | 0.34 | 850000000 | 5000000 | Core Face: Interior | 5 | 0.85
13341 | 500 | 0.085 | 212500000 | 1250000 | Wall Centerline | 1.25 | 0.2125

# IfcWallStandardCase: Basic Wall:NLRS_21_WA_Naturoll 037_170x580x4600mm (2)
In: Begane grond
Type - PredefinedType: STANDARD; Material: Knauf Insulation_Ecose® glaswol_naturoll 037 170 mm
Type - Analytical Properties - Roughness: 1; Thermal mass: 0; Absorptance: 0.1; Heat Transfer Coefficient (U): 0.205882; Thermal Resistance (R): 4.85714
Type - Construction - Function: Exterior; Wrapping at Inserts: Do not wrap; Width: 170 mm
Type - Data - rollen / pak: 2; pak (m2): 5.34; pakken / pallet: 24; pallet (m2): 128.06
Type - Energy Analysis - kortstondige waterabsorptie: WS; langdurige waterabsorptie: WL(P); luchtstroomweerstand: Afr5; warmtegeleidingscoëfficiënt: 0.035; warmteweerstand: 4.55
Type - General - NLRS_C_content_creator: Cadix; NLRS_C_content_versie: V1.0
Type - Graphics - Coarse Scale Fill Color: 0
Type - Identity Data - Type Image: Raster image: Naturoll 037.jpg (3); Assembly Code: 21; Assembly Description: Buitenwanden; Description: Naturoll 037 - 170mm; DoP nummer (Declaration of performance): G4220JPCPR; email: customerservice.nl@knaufinsulation.com; Manufacturer: Knauf Insulation B.V.; Model: Naturoll 037 is een onbeklede glaswoldeken met ECOSE® Technology; NLRS_C_Code_Brandklasse: A1; phone: +31(0)162-421245; product URL: https://www.knaufinsulation.nl/producten-van-knauf-insulation/naturoll-037; Type Name: NLRS_21_WA_Naturoll 037_170x580x4600mm; URL: www.knaufinsulation.nl
Type - Model Properties - diktebereik: 20-370; diktetolerantie: T2
Type - Other - Category: Walls; Family Name: Basic Wall
Type - Pset_ElementShading - Roughness: 304.8 mm
Type - Pset_ManufacturerTypeInformation - Manufacturer: Knauf Insulation B.V.
Type - Pset_ProductRequirements - Category: Walls
Type - Pset_QuantityTakeOff - Reference: NLRS_21_WA_Naturoll 037_170x580x4600mm
Type - Pset_ReinforcementBarPitchOfWall - Description: Naturoll 037 - 170mm; Reference: NLRS_21_WA_Naturoll 037_170x580x4600mm
Type - Pset_WallCommon - IsExternal: no; Reference: NLRS_21_WA_Naturoll 037_170x580x4600mm; ThermalTransmittance: 0.205882 kg/K/s3
Classification: 21 Buitenwanden (Uniformat)
BaseQuantities - Height: 2500 mm; Width: 170 mm
Constraints - Related to Mass: no; Room Bounding: yes; Base Constraint: Level: Begane grond; Base Extension Distance: 0 mm; Base is Attached: no; Base Offset: 0 mm; Top Constraint: Level: Lengte; Top Extension Distance: 0 mm; Top is Attached: no; Top Offset: 0 mm; Unconnected Height: 2500 mm
Other - Family: Basic Wall: NLRS_21_WA_Naturoll 037_170x580x4600mm; Family and Type: Basic Wall: NLRS_21_WA_Naturoll 037_170x580x4600mm; Type: Basic Wall: NLRS_21_WA_Naturoll 037_170x580x4600mm; Type Id: Basic Wall: NLRS_21_WA_Naturoll 037_170x580x4600mm
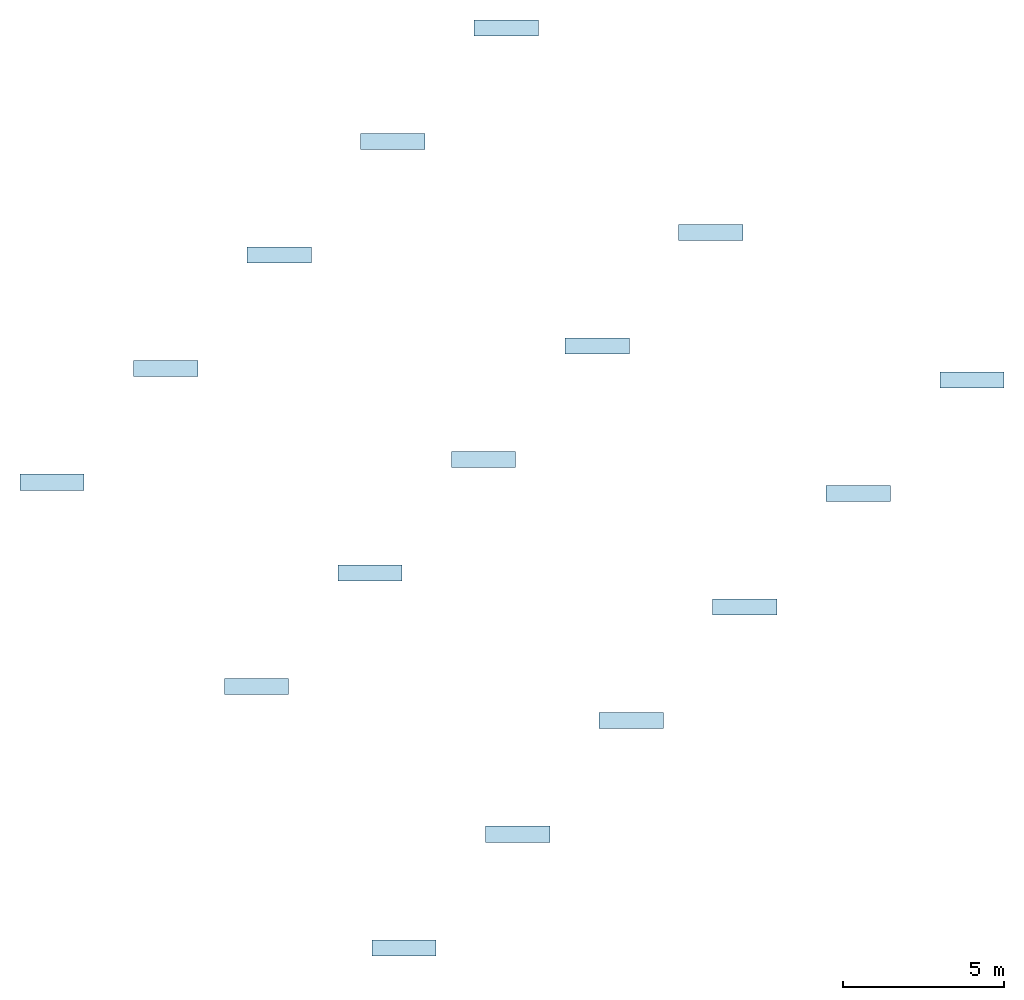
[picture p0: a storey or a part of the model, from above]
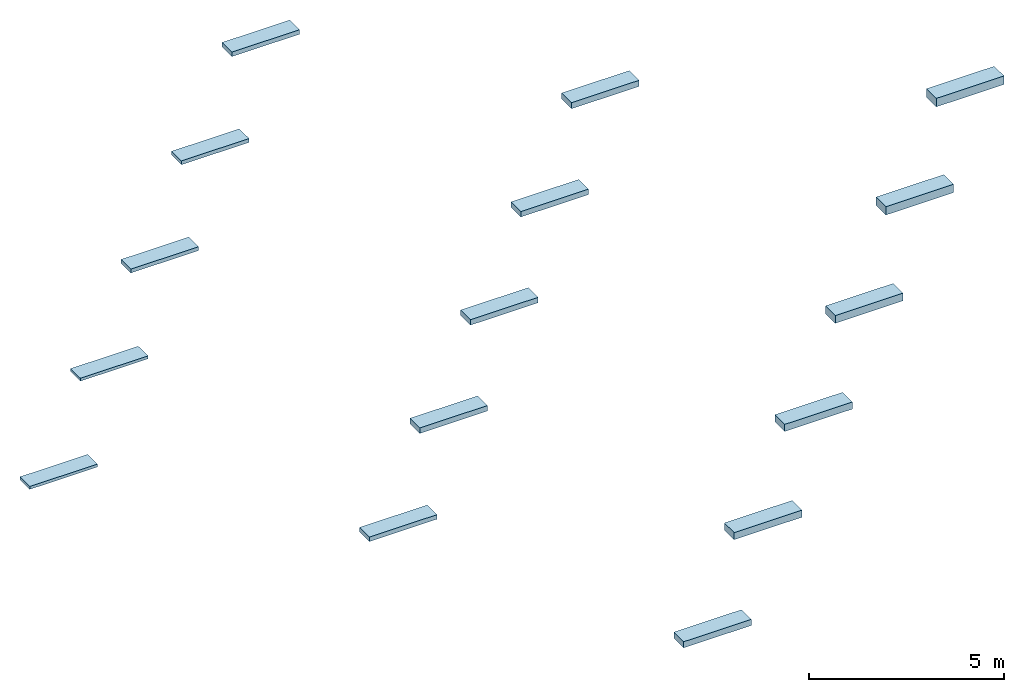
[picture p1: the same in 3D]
Properties of the parts of a building model (IFC2X3), part 3 of 3

# IfcWallStandardCase: Basic Wall:NLRS_21_WA_Naturoll 037_170x580x4600mm (2)
Phasing - Phase Created: New Construction
Structural - Enable Analytical Model: no; Structural: no; Structural Usage: Non-bearing
Pset_WallCommon - LoadBearing: no; IsExternal: yes; ExtendToStructure: no
Name (Basic Wall:NLRS_21_WA_Naturoll 037_170x580x4600mm:...) | BaseQuantities, Length (mm) = Dimensions, Length (mm) | GrossFootprintArea (m2) | NetVolume (m3) | NetSideArea (m2) | Location Line | Area (m2) | Volume (m3)
13361 | 2000 | 0.34 | 850000000 | 5000000 | Core Face: Interior | 5 | 0.85
13363 | 500 | 0.085 | 212500000 | 1250000 | Wall Centerline | 1.25 | 0.2125

# IfcWallStandardCase: Basic Wall:NLRS_21_WA_Naturoll 037_170x590x4600mm (2)
In: Begane grond
Type - PredefinedType: STANDARD; Material: Knauf Insulation_Ecose® glaswol_naturoll 037 170 mm
Type - Analytical Properties - Roughness: 1; Thermal mass: 0; Absorptance: 0.1; Heat Transfer Coefficient (U): 0.205882; Thermal Resistance (R): 4.85714
Type - Construction - Function: Exterior; Wrapping at Inserts: Do not wrap; Width: 170 mm
Type - Data - rollen / pak: 2; pak (m2): 5.43; pakken / pallet: 24; pallet (m2): 130.27
Type - Energy Analysis - kortstondige waterabsorptie: WS; langdurige waterabsorptie: WL(P); luchtstroomweerstand: Afr5; warmtegeleidingscoëfficiënt: 0.035; warmteweerstand: 4.55
Type - General - NLRS_C_content_creator: Cadix; NLRS_C_content_versie: V1.0
Type - Graphics - Coarse Scale Fill Color: 0
Type - Identity Data - Type Image: Raster image: Naturoll 037.jpg (3); Assembly Code: 21; Assembly Description: Buitenwanden; Description: Naturoll 037 - 170mm; DoP nummer (Declaration of performance): G4220JPCPR; email: customerservice.nl@knaufinsulation.com; Manufacturer: Knauf Insulation B.V.; Model: Naturoll 037 is een onbeklede glaswoldeken met ECOSE® Technology; NLRS_C_Code_Brandklasse: A1; phone: +31(0)162-421245; product URL: https://www.knaufinsulation.nl/producten-van-knauf-insulation/naturoll-037; Type Name: NLRS_21_WA_Naturoll 037_170x590x4600mm; URL: www.knaufinsulation.nl
Type - Model Properties - diktebereik: 20-370; diktetolerantie: T2
Type - Other - Category: Walls; Family Name: Basic Wall
Type - Pset_ElementShading - Roughness: 304.8 mm
Type - Pset_ManufacturerTypeInformation - Manufacturer: Knauf Insulation B.V.
Type - Pset_ProductRequirements - Category: Walls
Type - Pset_QuantityTakeOff - Reference: NLRS_21_WA_Naturoll 037_170x590x4600mm
Type - Pset_ReinforcementBarPitchOfWall - Description: Naturoll 037 - 170mm; Reference: NLRS_21_WA_Naturoll 037_170x590x4600mm
Type - Pset_WallCommon - IsExternal: no; Reference: NLRS_21_WA_Naturoll 037_170x590x4600mm; ThermalTransmittance: 0.205882 kg/K/s3
Classification: 21 Buitenwanden (Uniformat)
BaseQuantities - Height: 2500 mm; Width: 170 mm
Constraints - Related to Mass: no; Room Bounding: yes; Base Constraint: Level: Begane grond; Base Extension Distance: 0 mm; Base is Attached: no; Base Offset: 0 mm; Top Constraint: Level: Lengte; Top Extension Distance: 0 mm; Top is Attached: no; Top Offset: 0 mm; Unconnected Height: 2500 mm
Other - Family: Basic Wall: NLRS_21_WA_Naturoll 037_170x590x4600mm; Family and Type: Basic Wall: NLRS_21_WA_Naturoll 037_170x590x4600mm; Type: Basic Wall: NLRS_21_WA_Naturoll 037_170x590x4600mm; Type Id: Basic Wall: NLRS_21_WA_Naturoll 037_170x590x4600mm
Phasing - Phase Created: New Construction
Structural - Enable Analytical Model: no; Structural: no; Structural Usage: Non-bearing
Pset_WallCommon - LoadBearing: no; IsExternal: yes; ExtendToStructure: no
Name (Basic Wall:NLRS_21_WA_Naturoll 037_170x590x4600mm:...) | BaseQuantities, Length (mm) = Dimensions, Length (mm) | GrossFootprintArea (m2) | NetVolume (m3) | NetSideArea (m2) | Location Line | Area (m2) | Volume (m3)
13383 | 2000 | 0.34 | 850000000 | 5000000 | Core Face: Interior | 5 | 0.85
13385 | 500 | 0.085 | 212500000 | 1250000 | Wall Centerline | 1.25 | 0.2125

# IfcWallStandardCase: Basic Wall:NLRS_21_WA_Naturoll 037_190x580x4100mm (2)
In: Begane grond
Type - PredefinedType: STANDARD; Material: Knauf Insulation_Ecose® glaswol_naturoll 037 190 mm
Type - Analytical Properties - Roughness: 1; Thermal mass: 0; Absorptance: 0.1; Heat Transfer Coefficient (U): 0.184211; Thermal Resistance (R): 5.42857
Type - Construction - Function: Exterior; Wrapping at Inserts: Do not wrap; Width: 190 mm
Type - Data - rollen / pak: 2; pak (m2): 4.76; pakken / pallet: 24; pallet (m2): 114.14
Type - Energy Analysis - kortstondige waterabsorptie: WS; langdurige waterabsorptie: WL(P); luchtstroomweerstand: Afr5; warmtegeleidingscoëfficiënt: 0.035; warmteweerstand: 5.1
Type - General - NLRS_C_content_creator: Cadix; NLRS_C_content_versie: V1.0
Type - Graphics - Coarse Scale Fill Color: 0
Type - Identity Data - Type Image: Raster image: Naturoll 037.jpg (3); Assembly Code: 21; Assembly Description: Buitenwanden; Description: Naturoll 037 - 190mm; DoP nummer (Declaration of performance): G4220JPCPR; email: customerservice.nl@knaufinsulation.com; Manufacturer: Knauf Insulation B.V.; Model: Naturoll 037 is een onbeklede glaswoldeken met ECOSE® Technology; NLRS_C_Code_Brandklasse: A1; phone: +31(0)162-421245; product URL: https://www.knaufinsulation.nl/producten-van-knauf-insulation/naturoll-037; Type Name: NLRS_21_WA_Naturoll 037_190x580x4100mm; URL: www.knaufinsulation.nl
Type - Model Properties - diktebereik: 20-370; diktetolerantie: T2
Type - Other - Category: Walls; Family Name: Basic Wall
Type - Pset_ElementShading - Roughness: 304.8 mm
Type - Pset_ManufacturerTypeInformation - Manufacturer: Knauf Insulation B.V.
Type - Pset_ProductRequirements - Category: Walls
Type - Pset_QuantityTakeOff - Reference: NLRS_21_WA_Naturoll 037_190x580x4100mm
Type - Pset_ReinforcementBarPitchOfWall - Description: Naturoll 037 - 190mm; Reference: NLRS_21_WA_Naturoll 037_190x580x4100mm
Type - Pset_WallCommon - IsExternal: no; Reference: NLRS_21_WA_Naturoll 037_190x580x4100mm; ThermalTransmittance: 0.184211 kg/K/s3
Classification: 21 Buitenwanden (Uniformat)
BaseQuantities - Height: 2500 mm; Width: 190 mm
Constraints - Related to Mass: no; Room Bounding: yes; Base Constraint: Level: Begane grond; Base Extension Distance: 0 mm; Base is Attached: no; Base Offset: 0 mm; Top Constraint: Level: Lengte; Top Extension Distance: 0 mm; Top is Attached: no; Top Offset: 0 mm; Unconnected Height: 2500 mm
Other - Family: Basic Wall: NLRS_21_WA_Naturoll 037_190x580x4100mm; Family and Type: Basic Wall: NLRS_21_WA_Naturoll 037_190x580x4100mm; Type: Basic Wall: NLRS_21_WA_Naturoll 037_190x580x4100mm; Type Id: Basic Wall: NLRS_21_WA_Naturoll 037_190x580x4100mm
Phasing - Phase Created: New Construction
Structural - Enable Analytical Model: no; Structural: no; Structural Usage: Non-bearing
Pset_WallCommon - LoadBearing: no; IsExternal: yes; ExtendToStructure: no
Name (Basic Wall:NLRS_21_WA_Naturoll 037_190x580x4100mm:...) | BaseQuantities, Length (mm) = Dimensions, Length (mm) | GrossFootprintArea (m2) | NetVolume (m3) | NetSideArea (m2) | Location Line | Area (m2) | Volume (m3)
13405 | 2000 | 0.38 | 950000000 | 5000000 | Core Face: Interior | 5 | 0.95
13407 | 500 | 0.095 | 237500000 | 1250000 | Wall Centerline | 1.25 | 0.2375

# IfcWallStandardCase: Basic Wall:NLRS_21_WA_Naturoll 037_190x590x4100mm (2)
In: Begane grond
Type - PredefinedType: STANDARD; Material: Knauf Insulation_Ecose® glaswol_naturoll 037 190 mm
Type - Analytical Properties - Roughness: 1; Thermal mass: 0; Absorptance: 0.1; Heat Transfer Coefficient (U): 0.184211; Thermal Resistance (R): 5.42857
Type - Construction - Function: Exterior; Wrapping at Inserts: Do not wrap; Width: 190 mm
Type - Data - rollen / pak: 2; pak (m2): 4.84; pakken / pallet: 24; pallet (m2): 116.11
Type - Energy Analysis - kortstondige waterabsorptie: WS; langdurige waterabsorptie: WL(P); luchtstroomweerstand: Afr5; warmtegeleidingscoëfficiënt: 0.035; warmteweerstand: 5.1
Type - General - NLRS_C_content_creator: Cadix; NLRS_C_content_versie: V1.0
Type - Graphics - Coarse Scale Fill Color: 0
Type - Identity Data - Type Image: Raster image: Naturoll 037.jpg (3); Assembly Code: 21; Assembly Description: Buitenwanden; Description: Naturoll 037 - 190mm; DoP nummer (Declaration of performance): G4220JPCPR; email: customerservice.nl@knaufinsulation.com; Manufacturer: Knauf Insulation B.V.; Model: Naturoll 037 is een onbeklede glaswoldeken met ECOSE® Technology; NLRS_C_Code_Brandklasse: A1; phone: +31(0)162-421245; product URL: https://www.knaufinsulation.nl/producten-van-knauf-insulation/naturoll-037; Type Name: NLRS_21_WA_Naturoll 037_190x590x4100mm; URL: www.knaufinsulation.nl
Type - Model Properties - diktebereik: 20-370; diktetolerantie: T2
Type - Other - Category: Walls; Family Name: Basic Wall
Type - Pset_ElementShading - Roughness: 304.8 mm
Type - Pset_ManufacturerTypeInformation - Manufacturer: Knauf Insulation B.V.
Type - Pset_ProductRequirements - Category: Walls
Type - Pset_QuantityTakeOff - Reference: NLRS_21_WA_Naturoll 037_190x590x4100mm
Type - Pset_ReinforcementBarPitchOfWall - Description: Naturoll 037 - 190mm; Reference: NLRS_21_WA_Naturoll 037_190x590x4100mm
Type - Pset_WallCommon - IsExternal: no; Reference: NLRS_21_WA_Naturoll 037_190x590x4100mm; ThermalTransmittance: 0.184211 kg/K/s3
Classification: 21 Buitenwanden (Uniformat)
BaseQuantities - Height: 2500 mm; Width: 190 mm
Constraints - Related to Mass: no; Room Bounding: yes; Base Constraint: Level: Begane grond; Base Extension Distance: 0 mm; Base is Attached: no; Base Offset: 0 mm; Top Constraint: Level: Lengte; Top Extension Distance: 0 mm; Top is Attached: no; Top Offset: 0 mm; Unconnected Height: 2500 mm
Other - Family: Basic Wall: NLRS_21_WA_Naturoll 037_190x590x4100mm; Family and Type: Basic Wall: NLRS_21_WA_Naturoll 037_190x590x4100mm; Type: Basic Wall: NLRS_21_WA_Naturoll 037_190x590x4100mm; Type Id: Basic Wall: NLRS_21_WA_Naturoll 037_190x590x4100mm
Phasing - Phase Created: New Construction
Structural - Enable Analytical Model: no; Structural: no; Structural Usage: Non-bearing
Pset_WallCommon - LoadBearing: no; IsExternal: yes; ExtendToStructure: no
Name (Basic Wall:NLRS_21_WA_Naturoll 037_190x590x4100mm:...) | BaseQuantities, Length (mm) = Dimensions, Length (mm) | GrossFootprintArea (m2) | NetVolume (m3) | NetSideArea (m2) | Location Line | Area (m2) | Volume (m3)
13504 | 2000 | 0.38 | 950000000 | 5000000 | Core Face: Interior | 5 | 0.95
13506 | 500 | 0.095 | 237500000 | 1250000 | Wall Centerline | 1.25 | 0.2375

# IfcWallStandardCase: Basic Wall:NLRS_21_WA_Naturoll 037_220x580x3500mm (2)
In: Begane grond
Type - PredefinedType: STANDARD; Material: Knauf Insulation_Ecose® glaswol_naturoll 037 220 mm
Type - Analytical Properties - Roughness: 1; Thermal mass: 0; Absorptance: 0.1; Heat Transfer Coefficient (U): 0.159091; Thermal Resistance (R): 6.28571
Type - Construction - Function: Exterior; Wrapping at Inserts: Do not wrap; Width: 220 mm
Type - Data - rollen / pak: 2; pak (m2): 4.06; pakken / pallet: 24; pallet (m2): 97.44
Type - Energy Analysis - kortstondige waterabsorptie: WS; langdurige waterabsorptie: WL(P); luchtstroomweerstand: Afr5; warmtegeleidingscoëfficiënt: 0.035; warmteweerstand: 5.9
Type - General - NLRS_C_content_creator: Cadix; NLRS_C_content_versie: V1.0
Type - Graphics - Coarse Scale Fill Color: 0
Type - Identity Data - Type Image: Raster image: Naturoll 037.jpg (3); Assembly Code: 21; Assembly Description: Buitenwanden; Description: Naturoll 037 - 220mm; DoP nummer (Declaration of performance): G4220JPCPR; email: customerservice.nl@knaufinsulation.com; Manufacturer: Knauf Insulation B.V.; Model: Naturoll 037 is een onbeklede glaswoldeken met ECOSE® Technology; NLRS_C_Code_Brandklasse: A1; phone: +31(0)162-421245; product URL: https://www.knaufinsulation.nl/producten-van-knauf-insulation/naturoll-037; Type Name: NLRS_21_WA_Naturoll 037_220x580x3500mm; URL: www.knaufinsulation.nl
Type - Model Properties - diktebereik: 20-370; diktetolerantie: T2
Type - Other - Category: Walls; Family Name: Basic Wall
Type - Pset_ElementShading - Roughness: 304.8 mm
Type - Pset_ManufacturerTypeInformation - Manufacturer: Knauf Insulation B.V.
Type - Pset_ProductRequirements - Category: Walls
Type - Pset_QuantityTakeOff - Reference: NLRS_21_WA_Naturoll 037_220x580x3500mm
Type - Pset_ReinforcementBarPitchOfWall - Description: Naturoll 037 - 220mm; Reference: NLRS_21_WA_Naturoll 037_220x580x3500mm
Type - Pset_WallCommon - IsExternal: no; Reference: NLRS_21_WA_Naturoll 037_220x580x3500mm; ThermalTransmittance: 0.159091 kg/K/s3
Classification: 21 Buitenwanden (Uniformat)
BaseQuantities - Height: 2500 mm; Width: 220 mm
Constraints - Related to Mass: no; Room Bounding: yes; Base Constraint: Level: Begane grond; Base Extension Distance: 0 mm; Base is Attached: no; Base Offset: 0 mm; Top Constraint: Level: Lengte; Top Extension Distance: 0 mm; Top is Attached: no; Top Offset: 0 mm; Unconnected Height: 2500 mm
Other - Family: Basic Wall: NLRS_21_WA_Naturoll 037_220x580x3500mm; Family and Type: Basic Wall: NLRS_21_WA_Naturoll 037_220x580x3500mm; Type: Basic Wall: NLRS_21_WA_Naturoll 037_220x580x3500mm; Type Id: Basic Wall: NLRS_21_WA_Naturoll 037_220x580x3500mm
Phasing - Phase Created: New Construction
Structural - Enable Analytical Model: no; Structural: no; Structural Usage: Non-bearing
Pset_WallCommon - LoadBearing: no; IsExternal: yes; ExtendToStructure: no
Name (Basic Wall:NLRS_21_WA_Naturoll 037_220x580x3500mm:...) | BaseQuantities, Length (mm) = Dimensions, Length (mm) | GrossFootprintArea (m2) | NetVolume (m3) | NetSideArea (m2) | Location Line | Area (m2) | Volume (m3)
13524 | 2000 | 0.44 | 1100000000 | 5000000 | Core Face: Interior | 5 | 1.1
13526 | 500 | 0.11 | 275000000 | 1250000 | Wall Centerline | 1.25 | 0.275

# IfcWallStandardCase: Basic Wall:NLRS_21_WA_Naturoll 037_220x590x3500mm (2)
In: Begane grond
Type - PredefinedType: STANDARD; Material: Knauf Insulation_Ecose® glaswol_naturoll 037 220 mm
Type - Analytical Properties - Roughness: 1; Thermal mass: 0; Absorptance: 0.1; Heat Transfer Coefficient (U): 0.159091; Thermal Resistance (R): 6.28571
Type - Construction - Function: Exterior; Wrapping at Inserts: Do not wrap; Width: 220 mm
Type - Data - rollen / pak: 2; pak (m2): 4.13; pakken / pallet: 24; pallet (m2): 99.12
Type - Energy Analysis - kortstondige waterabsorptie: WS; langdurige waterabsorptie: WL(P); luchtstroomweerstand: Afr5; warmtegeleidingscoëfficiënt: 0.035; warmteweerstand: 5.9
Type - General - NLRS_C_content_creator: Cadix; NLRS_C_content_versie: V1.0
Type - Graphics - Coarse Scale Fill Color: 0
Type - Identity Data - Type Image: Raster image: Naturoll 037.jpg (3); Assembly Code: 21; Assembly Description: Buitenwanden; Description: Naturoll 037 - 220mm; DoP nummer (Declaration of performance): G4220JPCPR; email: customerservice.nl@knaufinsulation.com; Manufacturer: Knauf Insulation B.V.; Model: Naturoll 037 is een onbeklede glaswoldeken met ECOSE® Technology; NLRS_C_Code_Brandklasse: A1; phone: +31(0)162-421245; product URL: https://www.knaufinsulation.nl/producten-van-knauf-insulation/naturoll-037; Type Name: NLRS_21_WA_Naturoll 037_220x590x3500mm; URL: www.knaufinsulation.nl
Type - Model Properties - diktebereik: 20-370; diktetolerantie: T2
Type - Other - Category: Walls; Family Name: Basic Wall
Type - Pset_ElementShading - Roughness: 304.8 mm
Type - Pset_ManufacturerTypeInformation - Manufacturer: Knauf Insulation B.V.
Type - Pset_ProductRequirements - Category: Walls
Type - Pset_QuantityTakeOff - Reference: NLRS_21_WA_Naturoll 037_220x590x3500mm
Type - Pset_ReinforcementBarPitchOfWall - Description: Naturoll 037 - 220mm; Reference: NLRS_21_WA_Naturoll 037_220x590x3500mm
Type - Pset_WallCommon - IsExternal: no; Reference: NLRS_21_WA_Naturoll 037_220x590x3500mm; ThermalTransmittance: 0.159091 kg/K/s3
Classification: 21 Buitenwanden (Uniformat)
BaseQuantities - Height: 2500 mm; Width: 220 mm
Constraints - Related to Mass: no; Room Bounding: yes; Base Constraint: Level: Begane grond; Base Extension Distance: 0 mm; Base is Attached: no; Base Offset: 0 mm; Top Constraint: Level: Lengte; Top Extension Distance: 0 mm; Top is Attached: no; Top Offset: 0 mm; Unconnected Height: 2500 mm
Other - Family: Basic Wall: NLRS_21_WA_Naturoll 037_220x590x3500mm; Family and Type: Basic Wall: NLRS_21_WA_Naturoll 037_220x590x3500mm; Type: Basic Wall: NLRS_21_WA_Naturoll 037_220x590x3500mm; Type Id: Basic Wall: NLRS_21_WA_Naturoll 037_220x590x3500mm
Phasing - Phase Created: New Construction
Structural - Enable Analytical Model: no; Structural: no; Structural Usage: Non-bearing
Pset_WallCommon - LoadBearing: no; IsExternal: yes; ExtendToStructure: no
Name (Basic Wall:NLRS_21_WA_Naturoll 037_220x590x3500mm:...) | BaseQuantities, Length (mm) = Dimensions, Length (mm) | GrossFootprintArea (m2) | NetVolume (m3) | NetSideArea (m2) | Location Line | Area (m2) | Volume (m3)
13544 | 2000 | 0.44 | 1100000000 | 5000000 | Core Face: Interior | 5 | 1.1
13546 | 500 | 0.11 | 275000000 | 1250000 | Wall Centerline | 1.25 | 0.275

# IfcWallStandardCase: Basic Wall:NLRS_21_WA_Naturoll 037_240x590x3250mm (2)
In: Begane grond
Type - PredefinedType: STANDARD; Material: Knauf Insulation_Ecose® glaswol_naturoll 037 240 mm
Type - Analytical Properties - Roughness: 1; Thermal mass: 0; Absorptance: 0.1; Heat Transfer Coefficient (U): 0.145833; Thermal Resistance (R): 6.85714
Type - Construction - Function: Exterior; Wrapping at Inserts: Do not wrap; Width: 240 mm
Type - Data - rollen / pak: 3; pak (m2): 3.48; pakken / pallet: 24; pallet (m2): 92.04
Type - Energy Analysis - kortstondige waterabsorptie: WS; langdurige waterabsorptie: WL(P); luchtstroomweerstand: Afr5; warmtegeleidingscoëfficiënt: 0.035; warmteweerstand: 6.45
Type - General - NLRS_C_content_creator: Cadix; NLRS_C_content_versie: V1.0
Type - Graphics - Coarse Scale Fill Color: 0
Type - Identity Data - Type Image: Raster image: Naturoll 037.jpg (3); Assembly Code: 21; Assembly Description: Buitenwanden; Description: Naturoll 037 - 240mm; DoP nummer (Declaration of performance): G4220JPCPR; email: customerservice.nl@knaufinsulation.com; Manufacturer: Knauf Insulation B.V.; Model: Naturoll 037 is een onbeklede glaswoldeken met ECOSE® Technology; NLRS_C_Code_Brandklasse: A1; phone: +31(0)162-421245; product URL: https://www.knaufinsulation.nl/producten-van-knauf-insulation/naturoll-037; Type Name: NLRS_21_WA_Naturoll 037_240x590x3250mm; URL: www.knaufinsulation.nl
Type - Model Properties - diktebereik: 20-370; diktetolerantie: T2
Type - Other - Category: Walls; Family Name: Basic Wall
Type - Pset_ElementShading - Roughness: 304.8 mm
Type - Pset_ManufacturerTypeInformation - Manufacturer: Knauf Insulation B.V.
Type - Pset_ProductRequirements - Category: Walls
Type - Pset_QuantityTakeOff - Reference: NLRS_21_WA_Naturoll 037_240x590x3250mm
Type - Pset_ReinforcementBarPitchOfWall - Description: Naturoll 037 - 240mm; Reference: NLRS_21_WA_Naturoll 037_240x590x3250mm
Type - Pset_WallCommon - IsExternal: no; Reference: NLRS_21_WA_Naturoll 037_240x590x3250mm; ThermalTransmittance: 0.145833 kg/K/s3
Classification: 21 Buitenwanden (Uniformat)
BaseQuantities - Height: 2500 mm; Width: 240 mm
Constraints - Related to Mass: no; Room Bounding: yes; Base Constraint: Level: Begane grond; Base Extension Distance: 0 mm; Base is Attached: no; Base Offset: 0 mm; Top Constraint: Level: Lengte; Top Extension Distance: 0 mm; Top is Attached: no; Top Offset: 0 mm; Unconnected Height: 2500 mm
Other - Family: Basic Wall: NLRS_21_WA_Naturoll 037_240x590x3250mm; Family and Type: Basic Wall: NLRS_21_WA_Naturoll 037_240x590x3250mm; Type: Basic Wall: NLRS_21_WA_Naturoll 037_240x590x3250mm; Type Id: Basic Wall: NLRS_21_WA_Naturoll 037_240x590x3250mm
Phasing - Phase Created: New Construction
Structural - Enable Analytical Model: no; Structural: no; Structural Usage: Non-bearing
Pset_WallCommon - LoadBearing: no; IsExternal: yes; ExtendToStructure: no
Name (Basic Wall:NLRS_21_WA_Naturoll 037_240x590x3250mm:...) | BaseQuantities, Length (mm) = Dimensions, Length (mm) | GrossFootprintArea (m2) | NetVolume (m3) | NetSideArea (m2) | Location Line | Area (m2) | Volume (m3)
13564 | 2000 | 0.48 | 1200000000 | 5000000 | Core Face: Interior | 5 | 1.2
13566 | 500 | 0.12 | 300000000 | 1250000 | Wall Centerline | 1.25 | 0.3

# IfcWallStandardCase: Basic Wall:NLRS_21_WA_Naturoll 037_260x580x3000mm (2)
In: Begane grond
Type - PredefinedType: STANDARD; Material: Knauf Insulation_Ecose® glaswol_naturoll 037 260 mm
Type - Analytical Properties - Roughness: 1; Thermal mass: 0; Absorptance: 0.1; Heat Transfer Coefficient (U): 0.134615; Thermal Resistance (R): 7.42857
Type - Construction - Function: Exterior; Wrapping at Inserts: Do not wrap; Width: 260 mm
Type - Data - rollen / pak: 2; pak (m2): 3.48; pakken / pallet: 24; pallet (m2): 83.52
Type - Energy Analysis - warmteweerstand: 7; kortstondige waterabsorptie: WS; langdurige waterabsorptie: WL(P); luchtstroomweerstand: Afr5; warmtegeleidingscoëfficiënt: 0.035
Type - General - NLRS_C_content_creator: Cadix; NLRS_C_content_versie: V1.0
Type - Graphics - Coarse Scale Fill Color: 0
Type - Identity Data - Type Image: Raster image: Naturoll 037.jpg (3); Assembly Code: 21; Assembly Description: Buitenwanden; Description: Naturoll 037 - 260mm; DoP nummer (Declaration of performance): G4220JPCPR; email: customerservice.nl@knaufinsulation.com; Manufacturer: Knauf Insulation B.V.; Model: Naturoll 037 is een onbeklede glaswoldeken met ECOSE® Technology; NLRS_C_Code_Brandklasse: A1; phone: +31(0)162-421245; product URL: https://www.knaufinsulation.nl/producten-van-knauf-insulation/naturoll-037; Type Name: NLRS_21_WA_Naturoll 037_260x580x3000mm; URL: www.knaufinsulation.nl
Type - Model Properties - diktebereik: 20-370; diktetolerantie: T2
Type - Other - Category: Walls; Family Name: Basic Wall
Type - Pset_ElementShading - Roughness: 304.8 mm
Type - Pset_ManufacturerTypeInformation - Manufacturer: Knauf Insulation B.V.
Type - Pset_ProductRequirements - Category: Walls
Type - Pset_QuantityTakeOff - Reference: NLRS_21_WA_Naturoll 037_260x580x3000mm
Type - Pset_ReinforcementBarPitchOfWall - Description: Naturoll 037 - 260mm; Reference: NLRS_21_WA_Naturoll 037_260x580x3000mm
Type - Pset_WallCommon - IsExternal: no; Reference: NLRS_21_WA_Naturoll 037_260x580x3000mm; ThermalTransmittance: 0.134615 kg/K/s3
Classification: 21 Buitenwanden (Uniformat)
BaseQuantities - Height: 2500 mm; Width: 260 mm
Constraints - Related to Mass: no; Room Bounding: yes; Base Constraint: Level: Begane grond; Base Extension Distance: 0 mm; Base is Attached: no; Base Offset: 0 mm; Top Constraint: Level: Lengte; Top Extension Distance: 0 mm; Top is Attached: no; Top Offset: 0 mm; Unconnected Height: 2500 mm
Other - Family: Basic Wall: NLRS_21_WA_Naturoll 037_260x580x3000mm; Family and Type: Basic Wall: NLRS_21_WA_Naturoll 037_260x580x3000mm; Type: Basic Wall: NLRS_21_WA_Naturoll 037_260x580x3000mm; Type Id: Basic Wall: NLRS_21_WA_Naturoll 037_260x580x3000mm
Phasing - Phase Created: New Construction
Structural - Enable Analytical Model: no; Structural: no; Structural Usage: Non-bearing
Pset_WallCommon - LoadBearing: no; IsExternal: yes; ExtendToStructure: no
Name (Basic Wall:NLRS_21_WA_Naturoll 037_260x580x3000mm:...) | BaseQuantities, Length (mm) = Dimensions, Length (mm) | GrossFootprintArea (m2) | NetVolume (m3) | NetSideArea (m2) | Location Line | Area (m2) | Volume (m3)
13584 | 2000 | 0.52 | 1300000000 | 5000000 | Core Face: Interior | 5 | 1.3
13586 | 500 | 0.13 | 325000000 | 1250000 | Wall Centerline | 1.25 | 0.325

# IfcWallStandardCase: Basic Wall:NLRS_21_WA_Naturoll 037_265x590x3000mm (2)
In: Begane grond
Type - PredefinedType: STANDARD; Material: Knauf Insulation_Ecose® glaswol_naturoll 037 265 mm
Type - Analytical Properties - Roughness: 1; Thermal mass: 0; Absorptance: 0.1; Heat Transfer Coefficient (U): 0.132075; Thermal Resistance (R): 7.57143
Type - Construction - Function: Exterior; Wrapping at Inserts: Do not wrap; Width: 265 mm
Type - Data - rollen / pak: 2; pak (m2): 3.54; pakken / pallet: 24; pallet (m2): 84.96
Type - Energy Analysis - kortstondige waterabsorptie: WS; langdurige waterabsorptie: WL(P); luchtstroomweerstand: Afr5; warmtegeleidingscoëfficiënt: 0.035; warmteweerstand: 7.15
Type - General - NLRS_C_content_creator: Cadix; NLRS_C_content_versie: V1.0
Type - Graphics - Coarse Scale Fill Color: 0
Type - Identity Data - Type Image: Raster image: Naturoll 037.jpg (3); Assembly Code: 21; Assembly Description: Buitenwanden; Description: Naturoll 037 - 265mm; DoP nummer (Declaration of performance): G4220JPCPR; email: customerservice.nl@knaufinsulation.com; Manufacturer: Knauf Insulation B.V.; Model: Naturoll 037 is een onbeklede glaswoldeken met ECOSE® Technology; NLRS_C_Code_Brandklasse: A1; phone: +31(0)162-421245; product URL: https://www.knaufinsulation.nl/producten-van-knauf-insulation/naturoll-037; Type Name: NLRS_21_WA_Naturoll 037_265x590x3000mm; URL: www.knaufinsulation.nl
Type - Model Properties - diktebereik: 20-370; diktetolerantie: T2
Type - Other - Category: Walls; Family Name: Basic Wall
Type - Pset_ElementShading - Roughness: 304.8 mm
Type - Pset_ManufacturerTypeInformation - Manufacturer: Knauf Insulation B.V.
Type - Pset_ProductRequirements - Category: Walls
Type - Pset_QuantityTakeOff - Reference: NLRS_21_WA_Naturoll 037_265x590x3000mm
Type - Pset_ReinforcementBarPitchOfWall - Description: Naturoll 037 - 265mm; Reference: NLRS_21_WA_Naturoll 037_265x590x3000mm
Type - Pset_WallCommon - IsExternal: no; Reference: NLRS_21_WA_Naturoll 037_265x590x3000mm; ThermalTransmittance: 0.132075 kg/K/s3
Classification: 21 Buitenwanden (Uniformat)
BaseQuantities - Height: 2500 mm; Width: 265 mm
Constraints - Related to Mass: no; Room Bounding: yes; Base Constraint: Level: Begane grond; Base Extension Distance: 0 mm; Base is Attached: no; Base Offset: 0 mm; Top Constraint: Level: Lengte; Top Extension Distance: 0 mm; Top is Attached: no; Top Offset: 0 mm; Unconnected Height: 2500 mm
Other - Family: Basic Wall: NLRS_21_WA_Naturoll 037_265x590x3000mm; Family and Type: Basic Wall: NLRS_21_WA_Naturoll 037_265x590x3000mm; Type: Basic Wall: NLRS_21_WA_Naturoll 037_265x590x3000mm; Type Id: Basic Wall: NLRS_21_WA_Naturoll 037_265x590x3000mm
Phasing - Phase Created: New Construction
Structural - Enable Analytical Model: no; Structural: no; Structural Usage: Non-bearing
Pset_WallCommon - LoadBearing: no; IsExternal: yes; ExtendToStructure: no
Name (Basic Wall:NLRS_21_WA_Naturoll 037_265x590x3000mm:...) | BaseQuantities, Length (mm) = Dimensions, Length (mm) | GrossFootprintArea (m2) | NetVolume (m3) | NetSideArea (m2) | Location Line | Area (m2) | Volume (m3)
13722 | 2000 | 0.53 | 1325000000 | 5000000 | Core Face: Interior | 5 | 1.325
13724 | 500 | 0.1325 | 331250000 | 1250000 | Wall Centerline | 1.25 | 0.33125

# IfcWallStandardCase: Basic Wall:NLRS_21_WA_Naturoll 037_90x380x8200mm (2)
In: Begane grond
Type - PredefinedType: STANDARD; Material: Knauf Insulation_Ecose® glaswol_naturoll 037 90 mm
Type - Analytical Properties - Roughness: 1; Thermal mass: 0; Absorptance: 0.1; Heat Transfer Coefficient (U): 0.388889; Thermal Resistance (R): 2.57143
Type - Construction - Function: Exterior; Width: 90 mm; Wrapping at Inserts: Do not wrap
Type - Data - rollen / pak: 3; pak (m2): 9.35; pakken / pallet: 24; pallet (m2): 224.35
Type - Energy Analysis - kortstondige waterabsorptie: WS; langdurige waterabsorptie: WL(P); luchtstroomweerstand: Afr5; warmtegeleidingscoëfficiënt: 0.035; warmteweerstand: 2.4
Type - General - NLRS_C_content_creator: Cadix; NLRS_C_content_versie: V1.0
Type - Graphics - Coarse Scale Fill Color: 0
Type - Identity Data - Type Image: Raster image: Naturoll 037.jpg (3); Assembly Code: 21; Assembly Description: Buitenwanden; Description: Naturoll 037 - 90mm; DoP nummer (Declaration of performance): G4220JPCPR; email: customerservice.nl@knaufinsulation.com; Manufacturer: Knauf Insulation B.V.; Model: Naturoll 037 is een onbeklede glaswoldeken met ECOSE® Technology; NLRS_C_Code_Brandklasse: A1; phone: +31(0)162-421245; product URL: https://www.knaufinsulation.nl/producten-van-knauf-insulation/naturoll-037; Type Name: NLRS_21_WA_Naturoll 037_90x380x8200mm; URL: www.knaufinsulation.nl
Type - Model Properties - diktebereik: 20-370; diktetolerantie: T2
Type - Other - Category: Walls; Family Name: Basic Wall
Type - Pset_ElementShading - Roughness: 304.8 mm
Type - Pset_ManufacturerTypeInformation - Manufacturer: Knauf Insulation B.V.
Type - Pset_ProductRequirements - Category: Walls
Type - Pset_QuantityTakeOff - Reference: NLRS_21_WA_Naturoll 037_90x380x8200mm
Type - Pset_ReinforcementBarPitchOfWall - Description: Naturoll 037 - 90mm; Reference: NLRS_21_WA_Naturoll 037_90x380x8200mm
Type - Pset_WallCommon - IsExternal: no; Reference: NLRS_21_WA_Naturoll 037_90x380x8200mm; ThermalTransmittance: 0.388889 kg/K/s3
Classification: 21 Buitenwanden (Uniformat)
BaseQuantities - Height: 2500 mm; Width: 90 mm
Constraints - Related to Mass: no; Room Bounding: yes; Base Constraint: Level: Begane grond; Base Extension Distance: 0 mm; Base is Attached: no; Base Offset: 0 mm; Top Constraint: Level: Lengte; Top Extension Distance: 0 mm; Top is Attached: no; Top Offset: 0 mm; Unconnected Height: 2500 mm
Other - Family: Basic Wall: NLRS_21_WA_Naturoll 037_90x380x8200mm; Family and Type: Basic Wall: NLRS_21_WA_Naturoll 037_90x380x8200mm; Type: Basic Wall: NLRS_21_WA_Naturoll 037_90x380x8200mm; Type Id: Basic Wall: NLRS_21_WA_Naturoll 037_90x380x8200mm
Phasing - Phase Created: New Construction
Structural - Enable Analytical Model: no; Structural: no; Structural Usage: Non-bearing
Pset_WallCommon - LoadBearing: no; IsExternal: yes; ExtendToStructure: no
Name (Basic Wall:NLRS_21_WA_Naturoll 037_90x380x8200mm:...) | BaseQuantities, Length (mm) = Dimensions, Length (mm) | GrossFootprintArea (m2) | NetVolume (m3) | NetSideArea (m2) | Location Line | Area (m2) | Volume (m3)
11658 | 2000 | 0.18 | 450000000 | 5000000 | Core Face: Interior | 5 | 0.45
11746 | 500 | 0.045 | 112500000 | 1250000 | Wall Centerline | 1.25 | 0.1125

# IfcWallStandardCase: Basic Wall:NLRS_21_WA_Naturoll 037_90x580x8200mm (2)
In: Begane grond
Type - PredefinedType: STANDARD; Material: Knauf Insulation_Ecose® glaswol_naturoll 037 90 mm
Type - Analytical Properties - Roughness: 1; Thermal mass: 0; Absorptance: 0.1; Heat Transfer Coefficient (U): 0.388889; Thermal Resistance (R): 2.57143
Type - Construction - Function: Exterior; Wrapping at Inserts: Do not wrap; Width: 90 mm
Type - Data - rollen / pak: 2; pak (m2): 9.51; pakken / pallet: 24; pallet (m2): 228.29
Type - Energy Analysis - kortstondige waterabsorptie: WS; langdurige waterabsorptie: WL(P); luchtstroomweerstand: Afr5; warmtegeleidingscoëfficiënt: 0.035; warmteweerstand: 2.4
Type - General - NLRS_C_content_creator: Cadix; NLRS_C_content_versie: V1.0
Type - Graphics - Coarse Scale Fill Color: 0
Type - Identity Data - Type Image: Raster image: Naturoll 037.jpg (3); Assembly Code: 21; Assembly Description: Buitenwanden; Description: Naturoll 037 - 90mm; DoP nummer (Declaration of performance): G4220JPCPR; email: customerservice.nl@knaufinsulation.com; Manufacturer: Knauf Insulation B.V.; Model: Naturoll 037 is een onbeklede glaswoldeken met ECOSE® Technology; NLRS_C_Code_Brandklasse: A1; phone: +31(0)162-421245; product URL: https://www.knaufinsulation.nl/producten-van-knauf-insulation/naturoll-037; Type Name: NLRS_21_WA_Naturoll 037_90x580x8200mm; URL: www.knaufinsulation.nl
Type - Model Properties - diktebereik: 20-370; diktetolerantie: T2
Type - Other - Category: Walls; Family Name: Basic Wall
Type - Pset_ElementShading - Roughness: 304.8 mm
Type - Pset_ManufacturerTypeInformation - Manufacturer: Knauf Insulation B.V.
Type - Pset_ProductRequirements - Category: Walls
Type - Pset_QuantityTakeOff - Reference: NLRS_21_WA_Naturoll 037_90x580x8200mm
Type - Pset_ReinforcementBarPitchOfWall - Description: Naturoll 037 - 90mm; Reference: NLRS_21_WA_Naturoll 037_90x580x8200mm
Type - Pset_WallCommon - IsExternal: no; Reference: NLRS_21_WA_Naturoll 037_90x580x8200mm; ThermalTransmittance: 0.388889 kg/K/s3
Classification: 21 Buitenwanden (Uniformat)
BaseQuantities - Height: 2500 mm; Width: 90 mm
Constraints - Related to Mass: no; Room Bounding: yes; Base Constraint: Level: Begane grond; Base Extension Distance: 0 mm; Base is Attached: no; Base Offset: 0 mm; Top Constraint: Level: Lengte; Top Extension Distance: 0 mm; Top is Attached: no; Top Offset: 0 mm; Unconnected Height: 2500 mm
Other - Family: Basic Wall: NLRS_21_WA_Naturoll 037_90x580x8200mm; Family and Type: Basic Wall: NLRS_21_WA_Naturoll 037_90x580x8200mm; Type: Basic Wall: NLRS_21_WA_Naturoll 037_90x580x8200mm; Type Id: Basic Wall: NLRS_21_WA_Naturoll 037_90x580x8200mm
Phasing - Phase Created: New Construction
Structural - Enable Analytical Model: no; Structural: no; Structural Usage: Non-bearing
Pset_WallCommon - LoadBearing: no; IsExternal: yes; ExtendToStructure: no
Name (Basic Wall:NLRS_21_WA_Naturoll 037_90x580x8200mm:...) | BaseQuantities, Length (mm) = Dimensions, Length (mm) | GrossFootprintArea (m2) | NetVolume (m3) | NetSideArea (m2) | Location Line | Area (m2) | Volume (m3)
12982 | 2000 | 0.18 | 450000000 | 5000000 | Core Face: Interior | 5 | 0.45
12984 | 500 | 0.045 | 112500000 | 1250000 | Wall Centerline | 1.25 | 0.1125
